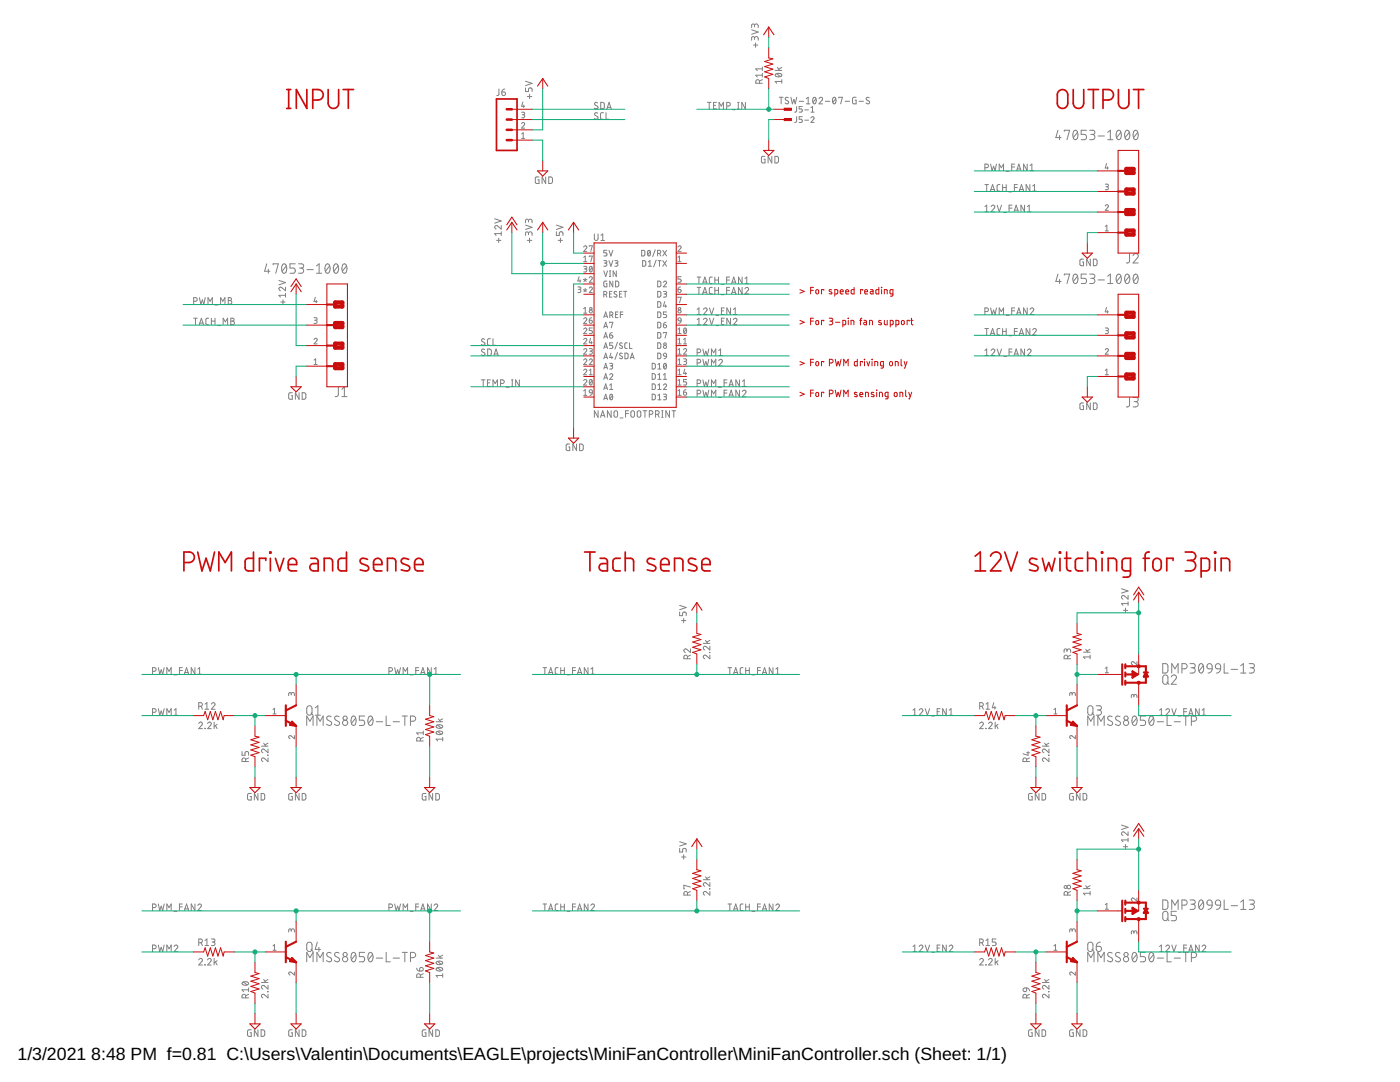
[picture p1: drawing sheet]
<svg xmlns="http://www.w3.org/2000/svg" width="279mm" height="216mm" viewBox="0 0 279 216" stroke-linecap="round" stroke-linejoin="round" font-family="sans-serif">
<defs><g id="words">
<g font-size="3.5">
<text x="3.5" y="211.4">1/3/2021</text>
<text x="18.2" y="211.4">8:48 PM f=0.81 C:\Users\Valentin\Documents\EAGLE\projects\MiniFanController\MiniFanController.sch (Sheet: 1/1)</text>
</g>
</g></defs>
<g fill="none" stroke="#808080" stroke-width=".2">
<path d="M99.6 17.8l-.1 1.1-.4 .2M100.1 18.4h.5a.37 .37 0 0 1 .3 .4 .37 .37 0 0 1-.4 .3 .37 .37 0 0 1-.4-.4zM100.7 17.8l-.3 .1-.3 .5M104.9 17.5v.8h.6v-.5a.36 .36 0 0 1 .3-.3 .36 .36 0 0 1 .4 .3v.5M104.9 16.2l1.3 .4-1.3 .5M105.2 19.3h.9M105.7 18.8v.9M150 5.9l1.3 .5-1.3 .4M150.4 9h.8M150.6 7.7a.37 .37 0 0 1 .4-.4 .37 .37 0 0 1 .3 .4v.3M150.6 7.9v-.4l-.4-.2-.2 .2v.5M150.6 5.1a.37 .37 0 0 1 .4-.3 .37 .37 0 0 1 .3 .3v.4"/>
<path d="M150.6 5.4v-.5l-.4-.1-.2 .1v.6M150.8 8.6v.8M151.6 16.6v-.3a.37 .37 0 0 0-.4-.4 .37 .37 0 0 0-.4 .4v.3h1.3M152.1 15.9l-.5 .3M152.1 15h-1.3l.3 .4M152.1 13.4v.7M152.1 14.6v.8M152.1 13.7h-1.3l.3 .4M154.7 14.1h1.3M154.8 14.8a.72 .72 0 0 1 1.2 .3 .84 .84 0 0 1-1.3-.1zM155 14.7l.7 .6M155.2 13.5l.4 .6"/>
<path d="M155.5 19.4h.8M155.9 19.4v1.3M156 16.3h-1.3l.3 .3M156 15.9v.7M156 13.5l-.6 .3M157.3 19.5l-.4-.1-.2 .3 .5 .5a.35 .35 0 0 1 0 .5 .35 .35 0 0 1-.5-.2M157.8 19.4l.3 1.3 .3-.9 .3 .9 .3-1.3M160.9 19.7l.4-.3v1.3M162.3 19.5l.1-.1a.66 .66 0 0 1 .5 .7 .66 .66 0 0 1-.5 .6l-.2-.6zM162.8 19.7l-.5 .7M163.4 19.7a.36 .36 0 0 1 .5-.3 .36 .36 0 0 1 .2 .6l-.7 .7h.8M166.3 19.5l.2-.1a.78 .78 0 0 1 0 1.3 .82 .82 0 0 1-.2-1.2z"/>
<path d="M166.8 19.7l-.6 .7M167.4 19.6v-.2h.7l-.3 1.3M170.9 19.4l-.7 .2-.1 .8 .2 .3h.6v-.7h-.3M173.5 19.5l-.5-.1-.1 .3 .5 .5a.35 .35 0 0 1 0 .5 .35 .35 0 0 1-.6-.2M104.1 24.7a.3 .3 0 0 1 .4-.2 .3 .3 0 0 1 .1 .4l-.5 .7h.6M104.1 22.4h.5l.1 .2-.1 .3h-.4M104.1 26.7l.3-.2v1.1M104.1 27.6h.6M104.4 20.3l-.3 .9h.6M104.4 22.9l.2 .1 .1 .3-.2 .2h-.4M104.5 21v.5M107.6 35.3l-.7 .1-.1 .9 .2 .3h.6v-.7h-.3"/>
<path d="M108.9 35.3v1.3l-.7-1.3v1.3M109.5 35.3h.5l.2 .2 .1 .7-.3 .4h-.5zM119.3 20.5l-.5-.1-.1 .3 .5 .5a.33 .33 0 0 1 0 .5 .33 .33 0 0 1-.5 0l-.1-.1M119.3 22.6a.33 .33 0 0 0-.5-.1 .33 .33 0 0 0 0 .5l.4 .2a.33 .33 0 0 1 0 .5 .33 .33 0 0 1-.5 0l-.1-.1M119.9 20.4l.5 .1 .2 .2v.8l-.2 .2h-.5zM120.4 22.5h-.4l-.2 .3 .1 .8 .5 .2M120.9 22.5v1.3h.6M121.1 21.7l.5-1.3 .4 1.3M121.2 21.4h.7M141.2 20.4h.7M141.5 20.4v1.3M142.4 21h.4"/>
<path d="M143 20.4h-.6v1.3h.6M143.5 21.7v-1.3l.4 .8 .5-.8v1.3M145 21.2h.4a.37 .37 0 0 0 .4-.4 .37 .37 0 0 0-.4-.4h-.4v1.3M146.2 21.9h.5M147.2 21.7h.3M147.2 20.4h.3M147.3 20.4v1.3M148.8 20.4v1.3l-.8-1.3v1.3M152.7 31.2l-.7 .1v.9l.1 .3h.6v-.7h-.2M154 31.2v1.3l-.7-1.3v1.3M154.6 31.2h.6l.1 .2v.9l-.1 .2h-.6zM159 21.3v.9l-.4 .2"/>
<path d="M159 23.3v1l-.4 .1M159.5 20.2h.9M160.1 21.3h-.6v.4h.4a.33 .33 0 0 1 .2 .4 .33 .33 0 0 1-.2 .3h-.4M160.1 23.3h-.6v.5h.4a.33 .33 0 0 1 .2 .3 .33 .33 0 0 1-.2 .3h-.4M160.6 21.9h.8M160.6 24h.8M160.9 20.7h.7M161.8 23.5a.31 .31 0 0 1 .5-.2 .31 .31 0 0 1 .1 .5l-.6 .6h.7M161.8 22.4h.7M161.8 21.5l.4-.2v1.1M164.7 20.2h.9M168.7 20.2h.8"/>
<path d="M171.4 20.2h.9M196.6 33.5h.3a.36 .36 0 0 0 .4-.4 .36 .36 0 0 0-.4-.4h-.3v1.4M196.6 36.8h.7M196.9 36.8v1.3M197.7 38.1l.4-1.3 .4 1.3M197.7 32.7l.3 1.4 .3-.9 .3 .9 .3-1.4M197.8 37.8h.6M199.4 34.1v-1.4l.4 .8 .5-.8v1.4M199.6 36.8l-.5 .1-.1 .2v.9l.6 .1M200.1 36.8v1.3M200.1 37.4h.7M200.8 34.2h.6"/>
<path d="M200.8 36.8v1.3M201.3 38.3h.6M201.9 33.3h.6M202.4 37.4h.6M202.5 32.7h-.6v1.4M202.9 34.1l.4-1.4 .5 1.4M203 33.7h.7M203 36.8h-.6v1.3M203.4 38.1l.5-1.3 .4 1.3M203.5 37.8h.7M205 32.7v1.4l-.7-1.4v1.4M205.5 36.8v1.3l-.7-1.3v1.3"/>
<path d="M205.6 33l.3-.3v1.4M205.6 34.1h.7M206.1 38.1h.7M206.1 37.1l.4-.3v1.3M211.1 26l-.4 1.5h1.1M211.5 27v.9M212.4 26.2v-.2h1.1l-.6 1.9M214.3 26.1l.3-.1a1.1 1.1 0 0 1 0 1.9 1.21 1.21 0 0 1-.3-1.8zM215 26.4l-.8 1.1M216.8 26h-1v.8h.6a.54 .54 0 0 1 .4 .5 .54 .54 0 0 1-.4 .6h-.6M217.5 26h.6a.41 .41 0 0 1 .4 .4 .41 .41 0 0 1-.4 .4h-.4M218 26.8a.53 .53 0 0 1 .5 .5 .53 .53 0 0 1-.5 .6h-.5"/>
<path d="M219.2 27.1h1.2M220.6 36.7l.5 .1 .1 .1-.1 .3-.4 .1M220.8 32.6l-.2 .9h.6M220.9 37.3l.2 .1v.4l-.5 .1M221 33.3v.5M221.1 27.9h1M221.1 26.4l.5-.4v1.9M223 26.1l.3-.1a1.1 1.1 0 0 1 0 1.9 1.17 1.17 0 0 1-.3-1.8zM223.7 26.4l-.9 1.1M224.7 26.1l.3-.1a1.1 1.1 0 0 1 0 1.9 1.19 1.19 0 0 1-.3-1.8zM225.4 26.4l-.9 1.1M226.4 26.1l.2-.1a1.1 1.1 0 0 1 0 1.9 1.21 1.21 0 0 1-.2-1.8z"/>
<path d="M227.1 26.4l-.9 1.1M39.8 59.4l.3 1.3 .3-.9 .3 .9 .3-1.3M45.6 59.4l.5 .1v.4l-.2 .1a.37 .37 0 0 1 .4 .3 .37 .37 0 0 1-.4 .4h-.3zM45.6 60h.3M53.2 52.6l-.4 1.5h1.1M53.6 53.7v.8M54.5 52.9v-.3h1l-.5 1.9M55.7 56l1.3 .4-1.3 .4M56.4 52.8l.3-.2a1.1 1.1 0 0 1 0 1.9 1.17 1.17 0 0 1-.3-1.7zM56.5 59.8v.9M57 57.3v.7l-.8-.6a.36 .36 0 0 0-.5 .1 .36 .36 0 0 0 .3 .5M57 58.9h-1.3l.3 .4"/>
<path d="M57 58.5v.8M57.1 53.1l-.8 1M58.9 52.6h-1v.9h.6a.53 .53 0 0 1 .4 .5 .53 .53 0 0 1-.4 .5h-.6M59.6 52.6h.6a.42 .42 0 0 1 .4 .5 .42 .42 0 0 1-.4 .4h-.4M60.1 53.5a.52 .52 0 0 1 .5 .5 .52 .52 0 0 1-.5 .5h-.5M61.3 53.8h1.2M62.9 59.3l-.2 .9h.6M63.1 59.9v.5M63.2 54.5h1M63.2 53.1l.5-.5v1.9M65.1 52.8l.3-.2a1.1 1.1 0 0 1 0 1.9 1.17 1.17 0 0 1-.3-1.7zM65.8 53.1l-.9 1"/>
<path d="M66.8 52.8l.3-.2a1.1 1.1 0 0 1 0 1.9 1.19 1.19 0 0 1-.3-1.7zM67.5 53.1l-.9 1M68.5 52.8l.2-.2a1.1 1.1 0 0 1 0 1.9 1.21 1.21 0 0 1-.2-1.7zM69.2 53.1l-.9 1M98.7 43.6l1.3 .5-1.3 .4M99.1 48h.9M99.5 47.5v.9M100 45v.7l-.7-.6a.36 .36 0 0 0-.5 .1 .36 .36 0 0 0 .2 .5M100 46.6h-1.3l.3 .4M100 46.2v.8M104.9 44.9l1.3 .5-1.3 .4M105.2 48h.9"/>
<path d="M105.5 46.6a.36 .36 0 0 1 .3-.4 .36 .36 0 0 1 .4 .4v.4M105.5 46.8l-.1-.4-.3-.1-.2 .1v.6M105.5 44.1a.36 .36 0 0 1 .3-.4 .36 .36 0 0 1 .4 .4v.3M105.5 44.3l-.1-.4-.3-.2-.2 .2v.5M105.7 47.5v.9M111 46.2v.8h.6v-.5a.38 .38 0 0 1 .4-.3 .38 .38 0 0 1 .4 .3v.5M111 44.9l1.4 .5-1.4 .4M111.4 48h.9M111.8 47.5v.9M115.3 57.3h.5l.1 .1-.1 .3h-.4M115.6 55.2l-.3 .9h.6M115.6 57.7l.3 .2v.2l-.1 .3h-.5"/>
<path d="M115.8 55.8v.5M116.4 57.8l.4 .1M116.4 55.8l.4 .1M116.5 53.1l.5 .1 .1 .1v.3l-.5 .1M116.5 49.3a.32 .32 0 0 1 .4-.2 .32 .32 0 0 1 .1 .5l-.5 .6h.6M116.5 52.2h.6M116.5 51.4l.3-.3v1.1M116.8 55.5v.4M116.8 57.6v.3M116.8 57.9l.2 .3M116.8 57.9l-.3 .3M116.8 55.9l.2 .3"/>
<path d="M116.8 55.9l-.3 .3M116.8 53.7l.3 .1v.4l-.6 .1M117.1 57.8l-.3 .1M117.1 55.8l-.3 .1M117.6 57.5a.3 .3 0 0 1 .4-.2 .3 .3 0 0 1 .1 .4l-.5 .7h.6M117.6 55.5a.3 .3 0 0 1 .4-.3 .3 .3 0 0 1 .1 .5l-.5 .6h.6M117.6 51.2v-.1h.6l-.3 1.1M117.6 49.2v-.2h.6l-.3 1.2M117.7 53.2l.2-.1a.65 .65 0 0 1 0 1.2 .74 .74 0 0 1-.2-1.1zM118.2 53.4l-.5 .6M118.6 46.7v.9a.37 .37 0 0 0 .4 .4 .37 .37 0 0 0 .4-.4v-.9M119.9 47l.4-.3v1.3"/>
<path d="M119.9 48h.7M120.5 58.8l.6-.1v-.4l-.6-.2v1.2M120.5 52h.5l.1 .2-.1 .3h-.4M120.5 54.1l.4 1.1 .3-1.1M120.8 52.5l.3 .2v.3l-.6 .1M120.9 58.8l.2 .5M121.1 56.1l-.6 .1v.8l.1 .2h.5v-.6h-.2M121.1 50h-.6v.4h.4a.33 .33 0 0 1 .2 .4 .33 .33 0 0 1-.2 .3h-.4M121.5 50l.4 1.1 .4-1.1M121.5 52l.4 1.1 .4-1.1M121.6 55.2h.3M121.6 54.1h.3"/>
<path d="M121.6 58.7h.4M121.8 54.1v1.1M122.1 58.1h-.5v1.2h.5M122.3 56.1v1.1l-.6-1.1v1.1M122.7 52h.5l.1 .2-.1 .3h-.4M122.9 56.1h.4l.2 .2v.7l-.2 .2h-.4zM123 54.1v1.1l-.6-1.1v1.1M123 52.5l.3 .1v.4l-.6 .1M123.1 58.3a.28 .28 0 0 0-.5-.1 .28 .28 0 0 0 .1 .4l.3 .2a.31 .31 0 0 1 0 .5 .31 .31 0 0 1-.5-.2M123.6 58.7h.4M124.1 58.1h-.5v1.2h.5M124.5 58.1h.6"/>
<path d="M124.8 58.1v1.2M128.1 50h.4l.2 .1v.8l-.2 .2h-.4zM128.2 52h.5l.2 .2v.7l-.2 .2h-.5zM129.3 50h.1a.56 .56 0 0 1 .4 .5 .56 .56 0 0 1-.4 .6l-.2-.6zM129.4 53.1h.6M129.4 52.3l.3-.3v1.1M129.8 50.2l-.5 .6M130.8 49.8l-.5 1.4M131 51.9l-.5 1.4M131.2 50.6l.6-.1v-.4l-.6-.1v1.1M131.3 56.1h.4l.2 .2v.7l-.2 .2h-.4zM131.3 58.1l.4 .1 .2 .1v.7l-.2 .2-.4 .1z"/>
<path d="M131.3 52h.6M131.6 50.6l.3 .5M131.6 52v1.1M132.3 50l.7 1.1M132.3 52l.7 1.1M132.4 56.3a.31 .31 0 0 1 .4-.2 .31 .31 0 0 1 .1 .5l-.5 .6h.6M132.4 58.1l.5 .1 .1 .2-.1 .2-.4 .1M132.7 58.7l.3 .1v.4l-.6 .1M133 50l-.7 1.1M133 52l-.7 1.1M135.3 49.3a.32 .32 0 0 1 .4-.2 .32 .32 0 0 1 .1 .5l-.5 .6h.6M135.3 57.7h.4a.32 .32 0 0 1 .2 .4 .32 .32 0 0 1-.3 .3 .32 .32 0 0 1-.3-.3z"/>
<path d="M135.3 51.4l.3-.3v1.1M135.3 52.2h.6M135.3 59.4v-.1h.6l-.3 1.1M135.8 57.3l-.4 .1-.1 .3M135.9 55.2h-.6v.5h.4a.32 .32 0 0 1 .2 .3 .32 .32 0 0 1-.2 .3h-.4M139.1 55.3h.7M139.1 57.3h.7M139.5 55.3v1.3M139.5 57.3v1.4M140.2 56.6l.5-1.3 .4 1.3M140.2 58.7l.5-1.4 .4 1.4M140.3 56.3h.7"/>
<path d="M140.3 58.3h.7M142.2 55.3h-.5l-.1 .3v.8l.6 .2M142.2 57.3l-.5 .1-.1 .2v.9l.6 .2M142.7 55.9h.7M142.7 55.3v1.3M142.7 57.3v1.4M142.7 57.9h.7M143.4 55.3v1.3M143.4 57.3v1.4M143.9 56.7h.6M143.9 58.8h.6M145 55.9h.6"/>
<path d="M145 57.9h.6M145.6 55.3h-.6v1.3M145.6 57.3h-.6v1.4M146 56.6l.4-1.3 .5 1.3M146 58.7l.4-1.4 .5 1.4M146.1 56.3h.7M146.1 58.3h.7M148.1 55.3v1.3l-.7-1.3v1.3M148.1 57.3v1.4l-.7-1.4v1.4M148.7 57.6a.36 .36 0 0 1 .5-.2 .36 .36 0 0 1 .1 .5l-.6 .8h.7M148.7 56.6h.7M148.7 55.6l.3-.3v1.3"/>
<path d="M196.6 41.2l.3-.3v1.3M196.6 42.2h.7M197.8 41.2a.37 .37 0 0 1 .5-.2 .37 .37 0 0 1 .1 .5l-.6 .7h.7M199 40.9l.4 1.3 .5-1.3M200.3 42.4h.6M201.4 41.5h.6M202 40.9h-.6v1.3M202.4 42.2l.4-1.3 .4 1.3M202.5 41.9h.6M204.5 40.9v1.3l-.7-1.3v1.3M205 42.2h.8M205 41.2l.4-.3v1.3"/>
<path d="M211.1 54.7l-.4 1.5h1.1M211.5 55.8v.8M212.4 54.9v-.2h1.1l-.6 1.9M214.3 54.8l.3-.1a1.1 1.1 0 0 1 0 1.9 1.21 1.21 0 0 1-.3-1.8zM215 55.1l-.8 1.1M216.2 51.7h-.5l-.1 .2-.1 .8 .2 .3h.5v-.7h-.2M216.8 54.7h-1v.8h.6a.53 .53 0 0 1 .4 .6 .53 .53 0 0 1-.4 .5h-.6M217.5 54.7h.6a.42 .42 0 0 1 .4 .4 .42 .42 0 0 1-.4 .4h-.4M217.6 51.7v1.3l-.7-1.3v1.3M218 55.5a.52 .52 0 0 1 .5 .6 .52 .52 0 0 1-.5 .5h-.5M218.2 51.7h.5l.2 .2v.7l-.2 .4h-.5zM219.2 55.9h1.2"/>
<path d="M220.6 41.1a.31 .31 0 0 1 .4-.2 .31 .31 0 0 1 .1 .4l-.5 .7h.6M220.6 45.2l.3-.3v1.2M220.6 46.1h.6M221.1 56.6h1M221.1 55.1l.5-.4v1.9M223 54.8l.3-.1a1.1 1.1 0 0 1 0 1.9 1.17 1.17 0 0 1-.3-1.8zM223.7 55.1l-.9 1.1M224.7 54.8l.3-.1a1.1 1.1 0 0 1 0 1.9 1.19 1.19 0 0 1-.3-1.8zM225.4 55.1l-.9 1.1M225.4 50.6v1.6l-.2 .3h-.4M226.1 51a.51 .51 0 0 1 .8-.4 .51 .51 0 0 1 .1 .8l-.9 1.1h1.1M226.4 54.8l.2-.1a1.1 1.1 0 0 1 0 1.9 1.21 1.21 0 0 1-.2-1.8z"/>
<path d="M227.1 55.1l-.9 1.1M38.7 60.1h.3a.36 .36 0 0 0 .4-.3 .36 .36 0 0 0-.4-.4h-.3v1.3M38.7 63.5h.7M39 63.5v1.3M39.8 64.8l.4-1.3 .4 1.3M39.9 64.5h.6M41.5 60.7v-1.3l.4 .7 .5-.7v1.3M41.7 63.5h-.4l-.2 .3v.8l.2 .2h.4M42.2 63.5v1.3M42.2 64.1h.7M42.9 60.9h.6M42.9 63.5v1.3"/>
<path d="M43.4 65h.6M44 60.7v-1.3l.5 .7 .4-.7v1.3M44.5 64.8v-1.3l.5 .7 .4-.7v1.3M46.1 63.5l.6 .1v.3l-.3 .2a.37 .37 0 0 1 .4 .3 .37 .37 0 0 1-.4 .4h-.3zM46.1 64.1h.3M56 60.3h.9M58.3 78.4l-.6 .1-.1 .9 .2 .3h.5v-.7h-.2M59.7 78.4v1.3l-.8-1.3v1.3M60.3 78.4h.5l.2 .2v.7l-.2 .4h-.5zM62.7 67.8a.31 .31 0 0 1 .4-.3 .31 .31 0 0 1 .1 .5l-.5 .6h.6M62.7 63.4h.5l.1 .2-.1 .3h-.4M62.7 72.7h.6"/>
<path d="M62.7 71.9l.3-.3v1.1M63 63.9l.2 .1v.4l-.5 .1M67.5 77.3v1.6l-.2 .2h-.4M68.2 79.1h1.1M68.2 77.7l.5-.4v1.8M96.1 75.8h.7M96.4 75.8v1.3M96.7 69.7h-.4l-.2 .2 .5 .5a.32 .32 0 0 1 .1 .5 .32 .32 0 0 1-.5 0l-.1-.1M96.7 67.7l-.4-.1-.2 .3 .5 .5a.32 .32 0 0 1 .1 .4 .32 .32 0 0 1-.5 0l-.1-.1M97.3 76.4h.4M97.3 69.6l.5 .1 .2 .2 .1 .7-.3 .3-.5 .1zM97.9 67.6h-.5l-.1 .3v.8l.2 .2h.4"/>
<path d="M97.9 75.8h-.6v1.3h.6M98.4 67.6v1.3h.6M98.4 77.1v-1.3l.4 .7 .5-.7v1.3M98.6 71l.4-1.4 .4 1.4M98.7 70.6h.6M99.9 76.5h.4a.36 .36 0 0 0 .3-.3 .36 .36 0 0 0-.3-.4h-.4v1.3M101 77.3h.6M102.1 75.8h.3M102.1 77.1h.3M102.2 75.8v1.3M103.7 75.8v1.3l-.8-1.3v1.3M116.5 75.9a.31 .31 0 0 1 .4-.2 .31 .31 0 0 1 .1 .5l-.5 .6h.6"/>
<path d="M116.5 73.9a.31 .31 0 0 1 .4-.2 .31 .31 0 0 1 .1 .4l-.5 .7h.6M116.5 71.9a.32 .32 0 0 1 .4-.3 .32 .32 0 0 1 .1 .5l-.5 .6h.6M116.5 69.8a.32 .32 0 0 1 .4-.2 .32 .32 0 0 1 .1 .5l-.5 .6h.6M116.5 67.8a.32 .32 0 0 1 .4-.3 .32 .32 0 0 1 .1 .5l-.5 .6h.6M116.5 65.7a.32 .32 0 0 1 .4-.2 .32 .32 0 0 1 .1 .5l-.5 .6h.6M116.5 63.6a.32 .32 0 0 1 .4-.2 .32 .32 0 0 1 .1 .5l-.5 .6h.6M116.5 61.6l.3-.3v1.2M116.5 78l.3-.3v1.2M116.5 78.9h.6M116.5 62.5h.6M117.6 71.9a.31 .31 0 0 1 .4-.3 .31 .31 0 0 1 .1 .5l-.5 .6h.6M117.6 69.6h.5l.1 .1-.1 .3-.4 .1"/>
<path d="M117.6 63.9h.4a.31 .31 0 0 1 .2 .3 .31 .31 0 0 1-.3 .3 .31 .31 0 0 1-.3-.3zM117.6 74.8h.6M117.6 73.9l.3-.2v1.1M117.7 77.8h.4l.1 .6-.5-.1zM117.7 75.8l.2-.1a.6 .6 0 0 1 .3 .6 .6 .6 0 0 1-.4 .5l-.2-.5zM117.9 67.5l-.3 .9h.6M117.9 70.1l.3 .1v.2l-.2 .3h-.4M118 68.1v.5M118.1 63.4l-.3 .1-.2 .4M118.2 75.9l-.5 .7M118.2 78.4l-.1 .3-.4 .2M118.2 65.4h-.6v.6h.4a.31 .31 0 0 1 .2 .3 .31 .31 0 0 1-.2 .3h-.4"/>
<path d="M120.5 79.8l.4-1.1 .3 1.1M120.5 77.7l.4-1.1 .3 1.1M120.5 75.7l.4-1.2 .3 1.2M120.5 73.6l.4-1.1 .3 1.1M120.5 71.6l.4-1.1 .3 1.1M120.5 69.5l.4-1.1 .3 1.1M120.5 67.5l.4-1.1 .3 1.1M120.5 65.4l.4-1.1 .3 1.1M120.5 63.4l.4-1.1 .3 1.1M120.6 79.5h.6M120.6 77.4h.6M120.6 75.4h.6"/>
<path d="M120.6 73.3h.6M120.6 71.3h.6M120.6 69.3h.6M120.6 67.2h.6M120.6 65.2h.6M120.6 63.1h.6M121.7 74.8a.31 .31 0 0 1 .4-.2 .31 .31 0 0 1 .1 .5l-.5 .6h.6M121.7 72.5h.3l.3 .2-.1 .3h-.4M121.7 66.9h.3a.31 .31 0 0 1 .3 .3 .31 .31 0 0 1-.4 .3 .31 .31 0 0 1-.2-.3zM121.7 64.4v-.1h.6l-.3 1.1M121.7 77.7h.6M121.7 76.9l.3-.3v1.1"/>
<path d="M121.7 62.9l.6-.1v-.4l-.6-.1v1.1M121.8 78.7h.1a.56 .56 0 0 1 .4 .5 .56 .56 0 0 1-.4 .6l-.2-.6zM121.9 70.5l-.2 .8h.6M122 73l.2 .1 .1 .3-.2 .2h-.4M122.1 62.9l.2 .5M122.1 71.1v.5M122.2 66.4l-.4 .1-.1 .4M122.2 78.9l-.5 .6M122.3 68.4h-.6v.5h.3a.32 .32 0 0 1 .3 .3 .32 .32 0 0 1-.3 .3h-.3M122.9 62.8h.3M123.2 70.3l-.5 1.4M123.2 68.3l-.5 1.4"/>
<path d="M123.3 62.3h-.4v1.1h.4M123.8 62.8h.5M124.2 70.5h-.4l-.1 .2 .5 .5v.2l-.2 .2-.4-.2M124.2 68.5l-.4-.1-.1 .3 .4 .4a.29 .29 0 0 1 0 .4 .29 .29 0 0 1-.4 0l-.1-.1M124.3 62.3h-.5v1.1M124.7 70.5h.5l.1 .2v.7l-.1 .2h-.5zM125.2 68.4h-.4l-.1 .3v.7l.5 .1M125.6 68.4v1.1h.6M125.8 71.6l.4-1.1 .4 1.1M125.9 71.3h.6M130.2 72.5h.3l.3 .2v.7l-.2 .2h-.4zM130.2 74.5l.4 .1 .2 .1v.8l-.3 .2h-.3z"/>
<path d="M130.2 76.6h.4l.2 .2v.7l-.2 .2h-.4zM130.2 78.7h.4l.2 .1v.8l-.2 .2h-.4zM131.3 60.2h.4l.2 .2v.6l-.2 .3h-.4zM131.3 62.3h.4l.2 .1v.7l-.2 .3h-.4zM131.3 64.3h.4l.2 .2v.7l-.2 .2h-.4zM131.3 66.4h.4l.2 .1v.8l-.2 .2h-.4zM131.3 68.4h.4l.2 .2v.7l-.2 .2h-.4zM131.3 70.5h.4l.2 .2v.7l-.2 .2h-.4zM131.3 72.7l.3-.2v1.1M131.3 74.8l.3-.3v1.2M131.3 76.9l.3-.3v1.1M131.3 78.9l.3-.2v1.1"/>
<path d="M131.3 73.6h.6M131.3 75.7h.6M131.3 77.7h.6M131.3 79.8h.6M132.4 64.8h.4a.31 .31 0 0 1 .2 .4 .31 .31 0 0 1-.3 .2 .31 .31 0 0 1-.3-.3zM132.4 76.9a.31 .31 0 0 1 .4-.3 .31 .31 0 0 1 .1 .5l-.5 .6h.6M132.4 78.7h.5l.1 .1-.1 .3-.4 .1M132.4 66.5v-.1h.6l-.3 1.1M132.4 75.7h.6M132.4 74.8l.3-.3v1.2M132.5 70.5h.4l.1 .6-.5-.1-.1-.2zM132.5 72.6l.1-.1a.58 .58 0 0 1 .4 .6 .58 .58 0 0 1-.4 .5l-.2-.5z"/>
<path d="M132.7 60.2l-.3 .9h.6M132.7 79.2l.3 .1v.4l-.6 .1M132.8 60.8v.5M132.9 64.3l-.4 .2-.1 .3M133 72.7l-.5 .7M133 62.3h-.6v.5h.4a.31 .31 0 0 1 .2 .3 .31 .31 0 0 1-.2 .3h-.4M133 71.1l-.1 .3-.4 .2M135.3 65.7l.3-.3v1.2M135.3 67.8l.3-.3v1.1M135.3 69.8l.3-.2v1.1M135.3 71.9l.3-.3v1.1M135.3 73.9l.3-.2v1.1"/>
<path d="M135.3 75.9l.3-.2v1.1M135.3 78l.3-.3v1.2M135.3 66.6h.6M135.3 68.6h.6M135.3 70.7h.6M135.3 72.7h.6M135.3 74.8h.6M135.3 76.8h.6M135.3 78.9h.6M135.4 63.5h.4l.1 .5-.6-.1zM135.9 64l-.2 .4-.3 .1M136.4 69.8a.31 .31 0 0 1 .5-.2 .31 .31 0 0 1 0 .5l-.5 .6h.6"/>
<path d="M136.4 71.6h.5l.1 .2v.2l-.5 .1M136.4 78.3h.4a.31 .31 0 0 1 .2 .3 .31 .31 0 0 1-.3 .3 .31 .31 0 0 1-.3-.3zM136.4 68.6h.6M136.4 67.8l.3-.3v1.1M136.5 65.5h.1a.58 .58 0 0 1 .4 .5 .58 .58 0 0 1-.4 .6l-.2-.6zM136.7 73.7l-.3 .8h.6M136.7 72.1l.3 .1v.3l-.1 .2h-.5M136.8 74.3v.5M136.9 77.7a.47 .47 0 0 0-.5 .6M137 65.7l-.5 .6M137 75.7h-.6v.5h.4a.32 .32 0 0 1 .2 .3 .32 .32 0 0 1-.2 .3h-.4M139.1 76.5h.4a.36 .36 0 0 0 .3-.3 .36 .36 0 0 0-.3-.4h-.4v1.3"/>
<path d="M139.1 78.6h.4a.36 .36 0 0 0 .3-.4 .36 .36 0 0 0-.3-.3h-.4v1.3M139.1 70.4h.4a.37 .37 0 0 0 .3-.4 .37 .37 0 0 0-.3-.4h-.4v1.4M139.1 72.4h.4a.37 .37 0 0 0 .3-.3 .37 .37 0 0 0-.3-.4h-.4v1.3M139.1 62.8h.7M139.1 64.8h.7M139.1 61.7l.4-.3v1.4M139.1 63.8l.4-.3v1.3M140.3 75.8l.3 1.3 .3-.9 .3 .9 .3-1.3M140.3 77.9l.3 1.3 .3-.9 .3 .9 .3-1.3M140.3 69.6l.3 1.4 .3-.9 .3 .9 .3-1.4M140.3 71.7l.3 1.3 .3-.9 .3 .9 .3-1.3M140.4 61.7a.36 .36 0 0 1 .5-.2 .36 .36 0 0 1 .1 .5l-.6 .8h.7"/>
<path d="M140.4 63.8a.36 .36 0 0 1 .5-.3 .36 .36 0 0 1 .1 .6l-.6 .7h.7M141.6 61.4l.4 1.4 .5-1.4M141.6 63.5l.4 1.3 .5-1.3M142 71v-1.4l.4 .8 .5-.8v1.4M142 73v-1.3l.4 .7 .5-.7v1.3M142 77.1v-1.3l.4 .7 .5-.7v1.3M142 79.2v-1.3l.4 .7 .5-.7v1.3M142.9 65h.5M142.9 62.9h.5M143.4 79.3h.6M143.4 77.3h.6M143.4 72a.36 .36 0 0 1 .6-.3 .36 .36 0 0 1 .1 .6l-.7 .7h.8"/>
<path d="M143.4 71h.8M143.4 69.9l.4-.3v1.4M144 64.1h.4M144 62h.4M144.5 76.4h.6M144.5 78.4h.6M144.5 61.4h-.5v1.4h.5M144.5 63.5h-.5v1.3h.5M145.1 75.8h-.6v1.3M145.1 77.9h-.6v1.3M145.5 77.1l.4-1.3 .4 1.3M145.5 79.2l.4-1.3 .4 1.3"/>
<path d="M145.6 76.8h.6M145.6 78.8h.6M145.8 61.4v1.4l-.7-1.4v1.4M145.8 63.5v1.3l-.7-1.3v1.3M146.4 63.8a.36 .36 0 0 1 .5-.3 .36 .36 0 0 1 .1 .6l-.6 .7h.7M146.4 62.8h.7M146.4 61.7l.3-.3v1.4M147.6 75.8v1.3l-.7-1.3v1.3M147.6 77.9v1.3l-.7-1.3v1.3M148.2 78.1a.35 .35 0 0 1 .5-.2 .35 .35 0 0 1 .1 .5l-.6 .8h.7M148.2 76.1l.3-.3v1.3M148.2 77.1h.7"/>
<path d="M196.6 62.2h.3a.36 .36 0 0 0 .4-.4 .36 .36 0 0 0-.4-.4h-.3v1.4M196.6 69.9l.3-.3v1.4M196.6 65.6h.7M196.6 71h.7M196.9 65.6v1.3M197.7 66.9l.4-1.3 .4 1.3M197.7 61.4l.3 1.4 .3-.9 .3 .9 .3-1.4M197.8 66.5h.6M197.8 69.9a.37 .37 0 0 1 .5-.2 .37 .37 0 0 1 .1 .5l-.6 .8h.7M199 69.6l.4 1.4 .5-1.4M199.4 62.8v-1.4l.4 .8 .5-.8v1.4M199.6 65.6h-.5l-.1 .2v.9l.2 .1 .4 .1"/>
<path d="M200.1 65.6v1.3M200.1 66.1h.7M200.3 71.1h.6M200.8 65.6v1.3M200.8 62.9h.6M201.3 67h.6M201.4 70.2h.6M201.9 62h.6M202 69.6h-.6v1.4M202.4 71l.4-1.4 .4 1.4M202.4 66.1h.6M202.5 70.6h.6"/>
<path d="M202.5 61.4h-.6v1.4M202.9 62.8l.4-1.4 .5 1.4M203 62.4h.7M203 65.6h-.6v1.3M203.4 66.9l.5-1.3 .4 1.3M203.5 66.5h.7M204.5 69.6v1.4l-.7-1.4v1.4M205 61.4v1.4l-.7-1.4v1.4M205 69.9a.37 .37 0 0 1 .6-.2 .37 .37 0 0 1 .1 .5l-.7 .8h.8M205.5 65.6v1.3l-.7-1.3v1.3M205.6 61.7a.36 .36 0 0 1 .5-.2 .36 .36 0 0 1 .1 .5l-.6 .8h.7M206.1 65.8a.36 .36 0 0 1 .5-.2 .36 .36 0 0 1 .1 .5l-.6 .8h.7"/>
<path d="M220.6 69.8a.31 .31 0 0 1 .4-.2 .31 .31 0 0 1 .1 .5l-.5 .6h.6M220.6 65.4l.5 .1 .1 .1-.1 .3-.4 .1M220.6 74.8h.6M220.6 73.9l.3-.2v1.1M220.8 61.3l-.2 .9h.6M220.9 66l.2 .1v.4l-.5 .1M221 62v.5M225.4 79.3v1.6l-.2 .3h-.4M226.1 79.3h.6a.41 .41 0 0 1 .5 .4 .41 .41 0 0 1-.5 .4h-.4M113.7 88.6l-.7 .2v.8l.2 .3h.5v-.7h-.2M115.1 88.6v1.3l-.8-1.3v1.3M115.7 88.6h.5l.2 .2v.9l-.2 .2h-.5z"/>
<path d="M119.4 82v1.3l-.8-1.3v1.3M119.8 83.3l.5-1.3 .4 1.3M120 82.9h.6M122 82v1.3l-.8-1.3v1.3M122.6 82.1l.4-.1 .2 .2 .1 .7a.36 .36 0 0 1-.4 .4 .36 .36 0 0 1-.4-.4zM123.7 83.4h.6M124.8 82.5h.6M125.4 82h-.6v1.3M126 82.1l.4-.1 .2 .2v.7a.36 .36 0 0 1-.3 .4 .36 .36 0 0 1-.4-.4zM127.3 82.1l.4-.1 .2 .2v.7a.36 .36 0 0 1-.4 .4 .36 .36 0 0 1-.3-.4zM128.3 82h.8M128.7 82v1.3"/>
<path d="M129.6 82.7h.3a.36 .36 0 0 0 .4-.4 .36 .36 0 0 0-.4-.3h-.3v1.3M130.8 82.7h.4a.36 .36 0 0 0 .4-.4 .36 .36 0 0 0-.4-.3h-.4v1.3M131.3 82.7l.3 .6M132.1 82h.2M132.1 83.3h.2M132.2 82v1.3M133.6 82v1.3l-.7-1.3v1.3M134.1 82h.7M134.5 82v1.3M216.2 80.4l-.6 .2-.1 .8 .2 .3h.5v-.7h-.2M217.6 80.4v1.3l-.7-1.3v1.3M218.2 80.4h.5l.2 .2v.8l-.2 .3h-.5z"/>
<path d="M226.6 80.1a.53 .53 0 0 1 .6 .6 .53 .53 0 0 1-.6 .5h-.5M223.8 117.5l1.3 .4-1.3 .4M225.1 118.8v.7l-.7-.6a.36 .36 0 0 0-.6 .1 .36 .36 0 0 0 .3 .5M30.4 133.9h.4a.36 .36 0 0 0 .4-.3 .36 .36 0 0 0-.4-.4h-.4v1.3M31.6 133.2l.3 1.3 .3-.9 .3 .9 .3-1.3M33.3 134.5v-1.3l.4 .7 .5-.7v1.3M34.7 134.7h.6M35.8 133.8h.6M36.4 133.2h-.6v1.3M36.8 134.5l.4-1.3 .5 1.3M36.9 134.2h.6M38.9 133.2v1.3l-.7-1.3v1.3"/>
<path d="M39.5 134.5h.7M39.5 133.5l.3-.3v1.3M58.1 138.5l.2-.3h.2l.2 .1 .1 .5M58.1 138.7v-.4l-.3-.1-.2 .2v.4M77.6 133.9h.4a.36 .36 0 0 0 .3-.3 .36 .36 0 0 0-.3-.4h-.4v1.3M78.8 133.2l.3 1.3 .3-.9 .2 .9 .3-1.3M80.5 134.5v-1.3l.4 .7 .4-.7v1.3M81.9 134.7h.5M83 133.8h.6M83.6 133.2h-.6v1.3M83.9 134.5l.5-1.3 .4 1.3M84.1 134.2h.6"/>
<path d="M86.1 133.2v1.3l-.8-1.3v1.3M86.6 133.5l.4-.3v1.3M86.6 134.5h.8M108.4 133.2h.7M108.7 133.2v1.3M109.5 134.5l.4-1.3 .4 1.3M109.6 134.2h.6M111.4 133.2h-.4l-.2 .3v.8l.6 .2M111.9 133.8h.7M111.9 133.2v1.3M112.6 133.2v1.3M113.2 134.7h.5"/>
<path d="M114.3 133.8h.6M114.9 133.2h-.6v1.3M115.2 134.5l.5-1.3 .4 1.3M115.3 134.2h.7M117.3 133.2v1.3l-.7-1.3v1.3M117.9 134.5h.7M117.9 133.5l.4-.3v1.3M135.6 122.1v.8h.6v-.5a.37 .37 0 0 1 .4-.3 .37 .37 0 0 1 .3 .3v.5M135.6 120.8l1.3 .4-1.3 .5M136 123.8h.9M136.4 123.4v.9M137.2 131.4v-.3a.36 .36 0 0 0-.4-.4 .36 .36 0 0 0-.3 .4v.3h1.3"/>
<path d="M137.8 129.5v.7l-.7-.6a.36 .36 0 0 0-.6 .1 .36 .36 0 0 0 .3 .5M137.8 130.7l-.6 .3M140.4 128.4h1.3M140.8 127.8l.4 .6M141.7 130.2h.1M141.7 130.7v.7l-.8-.6a.36 .36 0 0 0-.5 .1 .36 .36 0 0 0 .3 .5M141.7 128.9v.8l-.8-.6a.37 .37 0 0 0-.5 .1 .37 .37 0 0 0 .3 .5M141.7 127.8l-.6 .3M145.3 133.2h.7M145.6 133.2v1.3M146.4 134.5l.4-1.3 .5 1.3M146.5 134.2h.7"/>
<path d="M148.3 133.2h-.4l-.2 .3v.8l.6 .2M148.8 133.8h.7M148.8 133.2v1.3M149.5 133.2v1.3M150.1 134.7h.5M151.2 133.8h.6M151.8 133.2h-.6v1.3M152.1 134.5l.5-1.3 .4 1.3M152.3 134.2h.6M154.3 133.2v1.3l-.8-1.3v1.3M154.8 134.5h.8M154.8 133.5l.4-.3v1.3"/>
<path d="M212.9 129.8a.37 .37 0 0 1 .4-.3 .37 .37 0 0 1 .4 .3v.4M212.9 130v-.4l-.3-.1-.2 .1v.6M213.1 131.4v-.3a.36 .36 0 0 0-.4-.4 .36 .36 0 0 0-.3 .4v.3h1.3M213.7 130.7l-.6 .3M214 138.5l.1-.3h.3l.2 .1v.5M214 138.7v-.4l-.3-.1-.2 .1v.5M216.2 130.1h1.4M216.7 129.6l.4 .5M217.6 131.1h-1.4l.3 .3M217.6 130.7v.7M217.6 129.6l-.7 .3M220.6 133.4l.3-.3v1.1"/>
<path d="M220.6 134.2h.6M224.2 121.8h.9M224.6 121.3v.9M225.1 120.4h-1.3l.3 .4M225.1 120.1v.7M226.3 138.9l.1-.3h.3l.2 .1v.5M226.3 139.1l-.1-.5h-.2l-.2 .1v.5M226.9 132v.7l-.6-.6a.31 .31 0 0 0-.5 .1 .31 .31 0 0 0 .2 .5M232.1 132.4h.6l.4 .4v1.1l-.4 .4h-.6zM232.2 134.9l.3-.2 .5 .2 .1 1.1a.52 .52 0 0 1-.5 .6 .52 .52 0 0 1-.5-.6zM232.9 136.1l.4 .4M233.7 135.1a.52 .52 0 0 1 .8-.4 .52 .52 0 0 1 .1 .8l-.9 1h1.1"/>
<path d="M233.8 134.3v-1.9l.7 1.1 .6-1.1v1.9M235.9 133.5h.5a.52 .52 0 0 0 .5-.6 .52 .52 0 0 0-.5-.5h-.5v1.9M237.5 132.4h.6a.41 .41 0 0 1 .4 .4 .41 .41 0 0 1-.4 .4h-.4M238 133.2a.53 .53 0 0 1 .5 .6 .53 .53 0 0 1-.5 .5h-.5M239.4 132.5l.3-.1a1.13 1.13 0 0 1 0 1.9 1.19 1.19 0 0 1-.3-1.8zM240.1 132.8l-.8 1.1M241 132.6l.3-.2 .4 .1 .2 .3v.7l-.9-.2-.1-.3zM241.9 133.5l-.2 .5-.6 .3M242.7 132.6l.3-.2 .5 .2 .1 .9-.9-.2-.2-.3zM243.6 133.5l-.2 .5-.6 .3M244.3 132.4v1.9h.8M245.7 133.6h1.3"/>
<path d="M247.6 134.3h1.1M247.6 132.8l.5-.4v1.9M249.3 132.4h.6a.41 .41 0 0 1 .4 .4 .41 .41 0 0 1-.4 .4h-.4M249.8 133.2a.53 .53 0 0 1 .5 .6 .53 .53 0 0 1-.5 .5h-.5M30.4 142.1h.4a.36 .36 0 0 0 .4-.3 .36 .36 0 0 0-.4-.4h-.4v1.3M31.6 141.4l.3 1.3 .3-.8 .3 .8 .3-1.3M33.3 142.7v-1.3l.4 .7 .5-.7v1.3M34.8 142.7h.7M34.8 141.7l.3-.3v1.3M39.7 144.4a.36 .36 0 0 1 .5-.3 .36 .36 0 0 1 .1 .6l-.6 .7h.7M39.7 140.9h.3a.36 .36 0 0 0 .4-.3 .36 .36 0 0 0-.4-.4h-.3v1.3M40.1 140.9l.3 .6"/>
<path d="M40.9 145.3l.1 .1zM40.9 140.5l.4-.3v1.3M40.9 141.5h.8M41.4 144.4a.36 .36 0 0 1 .6-.3 .36 .36 0 0 1 .1 .6l-.7 .7h.8M42.2 140.5a.36 .36 0 0 1 .5-.3 .36 .36 0 0 1 .1 .6l-.6 .7h.7M42.7 144.1v1.3M43 144.8l.3 .6M43.3 144.5l-.6 .4M48.3 150v.7h.6v-.4a.36 .36 0 0 1 .4-.3 .36 .36 0 0 1 .3 .3v.4M49 152v-.4a.36 .36 0 0 0-.3-.4 .36 .36 0 0 0-.4 .4v.4h1.3M49.6 151.2l-.6 .3M50.1 158.3l-.7 .2v.9l.2 .2h.5v-.7h-.2"/>
<path d="M51.5 158.3v1.3l-.7-1.3v1.3M52.1 158.3l.5 .1 .2 .2v.8l-.2 .2h-.5zM52.2 148.9h1.3M52.6 148.3l.4 .6M53.4 150.7h.1zM53.5 151.2v.8l-.7-.7a.36 .36 0 0 0-.6 .1 .36 .36 0 0 0 .3 .6M53.5 149.5v.7l-.7-.6a.37 .37 0 0 0-.6 .1 .37 .37 0 0 0 .3 .5M53.5 148.3l-.6 .3M54.5 141.6l.3-.3v1.2M54.5 142.5h.6M58.3 158.3l-.6 .2-.1 .9 .2 .2h.5v-.7h-.2M58.8 146.8v.6l-.7-.5a.31 .31 0 0 0-.5 .1 .31 .31 0 0 0 .3 .4"/>
<path d="M59.7 158.3v1.3l-.8-1.3v1.3M60.3 158.3l.5 .1 .2 .2v.7l-.2 .3h-.5zM61.2 144.8v-1.9l.6 1 .7-1v1.9M61.3 141l.4-.2 .4 .2 .2 1.2a.53 .53 0 0 1-.6 .5 .53 .53 0 0 1-.5-.5zM62.1 142.3l.4 .4M62.9 141.2l.5-.4v1.9M62.9 142.7h1.1M63.2 144.8v-1.9l.7 1 .6-1v1.9M66.1 143a.47 .47 0 0 0-.7-.1 .47 .47 0 0 0 0 .8l.6 .3a.47 .47 0 0 1 .1 .7 .47 .47 0 0 1-.8-.1l-.1-.1M67.7 143a.47 .47 0 0 0-.8-.1 .47 .47 0 0 0 .1 .8l.6 .3a.47 .47 0 0 1 0 .7 .47 .47 0 0 1-.7-.1l-.2-.1M70.3 143l.3-.1a1.13 1.13 0 0 1 0 1.9 1.19 1.19 0 0 1-.3-1.8zM71 143.3l-.9 1"/>
<path d="M72.8 142.9h-1.1v.8h.6a.54 .54 0 0 1 .5 .5 .54 .54 0 0 1-.5 .6h-.6M73.6 143l.3-.1a1.1 1.1 0 0 1 0 1.9 1.19 1.19 0 0 1-.3-1.8zM74.4 143.3l-.9 1M75.1 144h1.3M77.1 142.9v1.9h.8M78.5 144h1.2M80.3 142.9h1M80.8 142.9v1.9M81.9 143.9h.5a.52 .52 0 0 0 .6-.5 .52 .52 0 0 0-.6-.5h-.5v1.9M83.9 147.8v-.3a.37 .37 0 0 0-.4-.4 .37 .37 0 0 0-.3 .4v.3h1.3M84.5 147.1l-.6 .3M84.5 146.2h-1.3l.3 .4"/>
<path d="M84.5 145.9v.7M85 158.3l-.7 .2v.9l.2 .2h.5v-.7h-.2M86.3 158.3v1.3l-.7-1.3v1.3M87 158.3l.5 .1 .2 .2v.8l-.2 .2h-.5zM87 144h1.3M87.1 146a.71 .71 0 0 1 1.2 .3 .82 .82 0 0 1-1.3-.1zM87.1 144.8a.73 .73 0 0 1 1.2 .3 .72 .72 0 0 1-1.2-.2zM87.3 145.9l.8 .6M87.3 144.7l.8 .6M87.5 143.4l.4 .6M88.3 147.5h-1.3l.3 .3M88.3 147.1v.7"/>
<path d="M88.3 143.4l-.6 .4M182.2 142.7h.7M182.2 141.7l.4-.3v1.3M183.5 141.7a.36 .36 0 0 1 .5-.3 .36 .36 0 0 1 .1 .6l-.6 .7h.7M184.6 141.4l.5 1.3 .4-1.3M185.9 142.9h.6M187 142h.5M187.6 141.4h-.6v1.3h.6M188.8 141.4v1.3l-.7-1.3v1.3M189.4 142.7h.8M189.4 141.7l.4-.3v1.3M195.5 144.4a.37 .37 0 0 1 .5-.3 .37 .37 0 0 1 .2 .6l-.7 .7h.8"/>
<path d="M195.5 140.9h.4a.36 .36 0 0 0 .4-.3 .36 .36 0 0 0-.4-.4h-.4v1.3M196 140.9l.3 .6M196.7 145.4h.1M196.8 141.5h.7M196.8 140.5l.3-.3v1.3M197.3 144.4a.36 .36 0 0 1 .5-.3 .36 .36 0 0 1 .1 .6l-.6 .7h.7M198.3 140.2l-.3 1h.8M198.5 140.9v.6M198.6 144.1v1.3M198.9 144.8l.3 .6M199.2 144.5l-.6 .4M204.9 152v-.4a.37 .37 0 0 0-.4-.4 .37 .37 0 0 0-.3 .4v.4h1.3"/>
<path d="M204.9 150.2h.6M205.2 150v.7l-1-.3M205.5 151.2l-.6 .3M206 158.3l-.7 .2v.9l.1 .2h.6v-.7h-.2M207.3 158.3v1.3l-.7-1.3v1.3M208 158.3l.5 .1 .2 .2v.8l-.2 .2h-.5zM208 148.9h1.3M208.5 148.3l.4 .6M209.3 150.7h.1M209.3 151.2v.8l-.7-.7a.36 .36 0 0 0-.5 .1 .36 .36 0 0 0 .2 .6M209.3 149.5v.7l-.7-.6a.36 .36 0 0 0-.5 .1 .36 .36 0 0 0 .2 .5M209.3 148.3l-.6 .3"/>
<path d="M210.3 142.5h.6M210.3 141.6l.4-.3v1.2M214.2 158.3l-.7 .2v.9l.2 .2h.5v-.7h-.2M214.6 146.8v.6l-.6-.5a.31 .31 0 0 0-.5 .1 .31 .31 0 0 0 .2 .4M215.5 158.3v1.3l-.7-1.3v1.3M216.2 158.3l.5 .1 .2 .2v.7l-.2 .3h-.5zM217.1 144.8v-1.9l.6 1 .6-1v1.9M217.2 141l.3-.2 .5 .2 .1 1.2a.52 .52 0 0 1-.5 .5 .52 .52 0 0 1-.5-.5zM217.9 142.3l.4 .4M218.8 140.8h.6a.42 .42 0 0 1 .4 .4 .42 .42 0 0 1-.4 .5h-.4M219.1 144.8v-1.9l.6 1 .7-1v1.9M219.3 141.7a.52 .52 0 0 1 .5 .5 .52 .52 0 0 1-.5 .5h-.5"/>
<path d="M222 143a.48 .48 0 0 0-.8-.1 .48 .48 0 0 0 .1 .8l.5 .3a.47 .47 0 0 1 .1 .7 .47 .47 0 0 1-.7-.1l-.2-.1M223.5 143a.47 .47 0 0 0-.7-.1 .47 .47 0 0 0 0 .8l.6 .3a.47 .47 0 0 1 .1 .7 .47 .47 0 0 1-.7-.1l-.2-.1M226.1 143l.3-.1a1.1 1.1 0 0 1 0 1.9 1.19 1.19 0 0 1-.3-1.8zM226.8 143.3l-.8 1M228.6 142.9h-1v.8h.6a.54 .54 0 0 1 .4 .5 .54 .54 0 0 1-.4 .6h-.6M229.5 143l.3-.1a1.1 1.1 0 0 1 0 1.9 1.17 1.17 0 0 1-.3-1.8zM230.2 143.3l-.8 1M230.9 144h1.3M231.4 141.7l.4-.3v1.3M231.4 142.7h.7M232.7 141.7a.37 .37 0 0 1 .5-.3 .37 .37 0 0 1 .1 .6l-.6 .7h.7M232.9 142.9v1.9h.9"/>
<path d="M233.9 141.4l.4 1.3 .4-1.3M234.3 144h1.3M235.1 142.9h.6M236.1 142.9h1.1M236.2 142h.6M236.6 142.9v1.9M236.8 141.4h-.6v1.3M237.2 142.7l.5-1.3 .4 1.3M237.3 142.4h.7M237.8 143.9h.5a.52 .52 0 0 0 .5-.5 .52 .52 0 0 0-.5-.5h-.5v1.9M239.3 141.4v1.3l-.7-1.3v1.3M239.9 142.7h.7"/>
<path d="M239.9 141.7l.4-.3v1.3M135.6 169.3v.7h.6v-.4a.37 .37 0 0 1 .4-.3 .37 .37 0 0 1 .3 .3v.4M135.6 168l1.3 .4-1.3 .4M136 171h.9M136.4 170.6v.8M137.2 178.6v-.4a.36 .36 0 0 0-.4-.3 .36 .36 0 0 0-.3 .3v.4h1.3M137.8 177l-1.3-.4v.8h.1M137.8 177.9l-.6 .3M140.4 175.5h1.3M140.8 175l.4 .5M141.7 177.3h.1M141.7 177.9v.7l-.8-.6a.36 .36 0 0 0-.5 .1 .36 .36 0 0 0 .3 .5"/>
<path d="M141.7 176.1v.7l-.8-.6a.36 .36 0 0 0-.5 .1 .36 .36 0 0 0 .3 .5M141.7 175l-.6 .3M213.1 178.6v-.4a.36 .36 0 0 0-.4-.3 .36 .36 0 0 0-.3 .3v.4h1.3M213.7 177.9l-.6 .3M216.2 177.3h1.4M216.7 176.7l.4 .6M217.6 177.9v.7M217.6 178.2h-1.4l.3 .4M217.6 176.7l-.7 .4M223.8 164.6l1.3 .5-1.3 .4M224.2 169h.9M224.6 168.5v.9"/>
<path d="M225.1 166v.7l-.7-.6a.36 .36 0 0 0-.6 .1 .36 .36 0 0 0 .3 .5M225.1 167.2v.8M225.1 167.6h-1.3l.3 .4M226.9 179.2v.6l-.6-.5a.31 .31 0 0 0-.5 .1 .31 .31 0 0 0 .2 .4M232.1 179.6h.6l.4 .3v1.2l-.4 .3-.6 .1zM237.5 179.6h.6a.42 .42 0 0 1 .4 .4 .42 .42 0 0 1-.4 .4h-.4M239.4 179.7l.3-.1a1.13 1.13 0 0 1 0 1.9 1.19 1.19 0 0 1-.3-1.8zM241 179.8l.3-.2h.4l.2 .3v.7l-.9-.1-.1-.3zM242.7 179.8l.3-.2 .5 .2 .1 .8-.9-.1-.2-.3zM244.3 179.6v1.9h.8M249.3 179.6h.6a.42 .42 0 0 1 .4 .4 .42 .42 0 0 1-.4 .4h-.4M30.4 181.1h.4a.36 .36 0 0 0 .4-.4 .36 .36 0 0 0-.4-.3h-.4v1.3"/>
<path d="M30.4 189.3h.4a.37 .37 0 0 0 .4-.4 .37 .37 0 0 0-.4-.3h-.4v1.3M31.6 180.4l.3 1.3 .3-.9 .3 .9 .3-1.3M31.6 188.6l.3 1.3 .3-.9 .3 .9 .3-1.3M33.3 181.7v-1.3l.4 .7 .5-.7v1.3M33.3 189.9v-1.3l.4 .7 .5-.7v1.3M34.7 181.8h.6M34.8 188.9a.36 .36 0 0 1 .5-.3 .36 .36 0 0 1 .1 .6l-.6 .7h.7M35.8 181h.6M36.4 180.4h-.6v1.3M36.8 181.7l.4-1.3 .5 1.3M36.9 181.4h.6M38.9 180.4v1.3l-.7-1.3v1.3"/>
<path d="M39.5 180.7a.36 .36 0 0 1 .5-.3 .36 .36 0 0 1 .1 .6l-.6 .7h.7M39.7 191.5a.36 .36 0 0 1 .5-.2 .36 .36 0 0 1 .1 .5l-.6 .8h.7M39.7 188.1h.3a.37 .37 0 0 0 .4-.4 .37 .37 0 0 0-.4-.3h-.3v1.3M40.1 188.1l.3 .6M40.9 192.5l.1 .1zM40.9 187.7l.4-.3v1.3M40.9 188.7h.8M41.4 191.5a.36 .36 0 0 1 .6-.2 .36 .36 0 0 1 .1 .5l-.7 .8h.8M42.2 187.4h.6l.1 .2-.1 .3-.5 .1M42.5 188a.36 .36 0 0 1 .4 .3 .36 .36 0 0 1-.4 .4h-.3M42.7 191.2v1.4M43 191.9l.3 .7"/>
<path d="M43.3 191.7l-.6 .4M48.4 196a.72 .72 0 0 1 1.2 .3 .72 .72 0 0 1-1.3-.2zM48.6 195.9l.7 .6M49 199.1v-.3a.36 .36 0 0 0-.3-.4 .36 .36 0 0 0-.4 .4v.3h1.3M49.6 197.1v.8M49.6 198.4l-.6 .3M49.6 197.5h-1.3l.3 .4M52.2 196h1.3M52.6 195.5l.4 .5M53.5 197.8h.1M53.5 198.4v.7l-.7-.6a.36 .36 0 0 0-.6 .1 .36 .36 0 0 0 .3 .5M53.5 196.6v.8l-.7-.7a.37 .37 0 0 0-.6 .1 .37 .37 0 0 0 .3 .6"/>
<path d="M53.5 195.5l-.6 .3M54.5 188.7l.3-.2v1.1M54.5 189.6h.6M58.1 185.7l.2-.3 .2-.1 .2 .2 .1 .5M58.1 185.8v-.3l-.3-.2-.2 .3v.4M58.8 194v.6l-.7-.6a.31 .31 0 0 0-.5 .1 .31 .31 0 0 0 .3 .5M61.2 191.9v-1.9l.6 1.1 .7-1.1v1.9M61.3 188.2l.4-.2 .4 .2 .2 1.2a.53 .53 0 0 1-.6 .5 .53 .53 0 0 1-.5-.5zM62.1 189.4l.4 .5M63.2 191.9v-1.9l.7 1.1 .6-1.1v1.9M63.3 188l-.4 1.4h1.1M63.6 189v.9"/>
<path d="M66.1 190.2a.47 .47 0 0 0-.7-.1 .47 .47 0 0 0 0 .7l.6 .3a.47 .47 0 0 1 .1 .7 .47 .47 0 0 1-.8 0l-.1-.1M67.7 190.2a.47 .47 0 0 0-.8-.1 .47 .47 0 0 0 .1 .7l.6 .3a.47 .47 0 0 1 0 .7 .47 .47 0 0 1-.7 0l-.2-.1M70.3 190.2l.3-.2a1.13 1.13 0 0 1 0 1.9 1.19 1.19 0 0 1-.3-1.7zM71 190.5l-.9 1M72.8 190h-1.1v.9h.6a.53 .53 0 0 1 .5 .5 .53 .53 0 0 1-.5 .5h-.6M73.6 190.2l.3-.2a1.1 1.1 0 0 1 0 1.9 1.19 1.19 0 0 1-.3-1.7zM74.4 190.5l-.9 1M75.1 191.2h1.3M77.1 190v1.9h.8M77.6 181.1h.4a.36 .36 0 0 0 .3-.4 .36 .36 0 0 0-.3-.3h-.4v1.3M78.5 191.2h1.2M78.8 180.4l.3 1.3 .3-.9 .2 .9 .3-1.3"/>
<path d="M80.3 190h1M80.5 181.7v-1.3l.4 .7 .4-.7v1.3M80.8 190v1.9M81.9 181.8h.5M81.9 191.1h.5a.53 .53 0 0 0 .6-.5 .53 .53 0 0 0-.6-.6h-.5v1.9M83 181h.6M83.2 193.2l.2 .5 .4 .1M83.6 180.4h-.6v1.3M83.8 193.1a.37 .37 0 0 1 .6 .1 .37 .37 0 0 1-.3 .6h-.3zM83.9 195v-.4a.37 .37 0 0 0-.4-.3 .37 .37 0 0 0-.3 .3v.4h1.3M83.9 181.7l.5-1.3 .4 1.3M84.1 181.4h.6"/>
<path d="M84.5 194.3l-.6 .3M86.1 180.4v1.3l-.8-1.3v1.3M86.6 180.7a.36 .36 0 0 1 .5-.3 .36 .36 0 0 1 .1 .6l-.6 .7h.8M87 191.2h1.3M87.1 193.2a.73 .73 0 0 1 1.2 .3 .72 .72 0 0 1-.7 .3 .72 .72 0 0 1-.5-.5zM87.1 191.9a.72 .72 0 0 1 1.2 .3 .72 .72 0 0 1-1.2-.2zM87.3 193.1l.8 .6M87.3 191.8l.8 .6M87.5 190.6l.4 .6M88.3 194.3v.7M88.3 194.6h-1.3l.3 .4M88.3 190.6l-.6 .3"/>
<path d="M108.4 180.4h.7M108.7 180.4v1.3M109.5 181.7l.4-1.3 .4 1.3M109.6 181.4h.6M111.4 180.4h-.4l-.2 .3v.8l.2 .2h.4M111.9 180.4v1.3M111.9 181h.7M112.6 180.4v1.3M113.2 181.8h.5M114.3 181h.6M114.9 180.4h-.6v1.3M115.2 181.7l.5-1.3 .4 1.3"/>
<path d="M115.3 181.4h.7M117.3 180.4v1.3l-.7-1.3v1.3M117.9 180.7a.36 .36 0 0 1 .5-.3 .36 .36 0 0 1 .1 .6l-.6 .7h.7M145.3 180.4h.7M145.6 180.4v1.3M146.4 181.7l.4-1.3 .5 1.3M146.5 181.4h.7M148.3 180.4h-.4l-.2 .3v.8l.2 .2h.4M148.8 180.4v1.3M148.8 181h.7M149.5 180.4v1.3M150.1 181.8h.5"/>
<path d="M151.2 181h.6M151.8 180.4h-.6v1.3M152.1 181.7l.5-1.3 .4 1.3M152.3 181.4h.6M154.3 180.4v1.3l-.8-1.3v1.3M154.8 180.7a.36 .36 0 0 1 .5-.3 .36 .36 0 0 1 .1 .6l-.6 .7h.8M182.2 189.9h.7M182.2 188.9l.4-.3v1.3M183.5 188.9a.36 .36 0 0 1 .5-.3 .36 .36 0 0 1 .1 .6l-.6 .7h.7M184.6 188.6l.5 1.3 .4-1.3M185.9 190h.6M187 189.2h.5"/>
<path d="M187.6 188.6h-.6v1.3h.6M188.8 188.6v1.3l-.7-1.3v1.3M189.4 188.9a.37 .37 0 0 1 .5-.3 .37 .37 0 0 1 .2 .6l-.7 .7h.8M195.5 191.5a.37 .37 0 0 1 .5-.2 .37 .37 0 0 1 .2 .5l-.7 .8h.8M195.5 188.1h.4a.37 .37 0 0 0 .4-.4 .37 .37 0 0 0-.4-.3h-.4v1.3M196 188.1l.3 .6M196.7 192.6h.1M196.8 188.7h.7M196.8 187.7l.3-.3v1.3M197.3 191.5a.36 .36 0 0 1 .5-.2 .36 .36 0 0 1 .1 .5l-.6 .8h.7M198.6 191.2v1.4M198.8 187.4h-.8v.6h.5a.36 .36 0 0 1 .3 .3 .36 .36 0 0 1-.3 .4h-.5"/>
<path d="M198.9 191.9l.3 .7M199.2 191.7l-.6 .4M204.3 197.3l.6-.2v.5a.37 .37 0 0 1-.5 .2 .37 .37 0 0 1-.1-.5zM204.9 199.1v-.3a.37 .37 0 0 0-.4-.4 .37 .37 0 0 0-.3 .4v.3h1.3M204.9 197.1l.5 .3 .1 .3M205.5 198.4l-.6 .3M208 196h1.3M208.5 195.5l.4 .5M209.3 197.8h.1M209.3 198.4v.7l-.7-.6a.36 .36 0 0 0-.5 .1 .36 .36 0 0 0 .2 .5M209.3 196.6v.8l-.7-.7a.36 .36 0 0 0-.5 .1 .36 .36 0 0 0 .2 .6M209.3 195.5l-.6 .3"/>
<path d="M210.3 188.7l.4-.2v1.1M210.3 189.6h.6M214 185.7l.1-.3 .3-.1 .2 .2v.5M214 185.8v-.3l-.3-.2-.2 .2v.5M214.6 194v.6l-.6-.6a.31 .31 0 0 0-.5 .1 .31 .31 0 0 0 .2 .5M217.1 191.9v-1.9l.6 1.1 .6-1.1v1.9M217.2 188.2l.3-.2 .5 .2 .1 1.2a.52 .52 0 0 1-.5 .5 .52 .52 0 0 1-.5-.5zM217.9 189.4l.4 .5M218.8 188.8h.6a.52 .52 0 0 1 .4 .6 .52 .52 0 0 1-.5 .5 .52 .52 0 0 1-.5-.5zM219.1 191.9v-1.9l.6 1.1 .7-1.1v1.9M219.6 188a.85 .85 0 0 0-.8 .8M220.6 180.5l.3-.2v1.1"/>
<path d="M220.6 181.4h.6M222 190.2a.48 .48 0 0 0-.8-.1 .48 .48 0 0 0 .1 .7l.5 .3a.47 .47 0 0 1 .1 .7 .47 .47 0 0 1-.7 0l-.2-.1M223.5 190.2a.47 .47 0 0 0-.7-.1 .47 .47 0 0 0 0 .7l.6 .3a.47 .47 0 0 1 .1 .7 .47 .47 0 0 1-.7 0l-.2-.1M226.1 190.2l.3-.2a1.1 1.1 0 0 1 0 1.9 1.19 1.19 0 0 1-.3-1.7zM226.3 186.1l.1-.3h.4l.1 .6M226.3 186.2v-.3l-.3-.2-.2 .2v.5M226.8 190.5l-.8 1M228.6 190h-1v.9h.6a.53 .53 0 0 1 .4 .5 .53 .53 0 0 1-.4 .5h-.6M229.5 190.2l.3-.2a1.1 1.1 0 0 1 0 1.9 1.17 1.17 0 0 1-.3-1.7zM230.2 190.5l-.8 1M230.9 191.2h1.3M231.4 188.9l.4-.3v1.3"/>
<path d="M231.4 189.9h.7M232.2 182l.3-.2 .5 .2 .1 1.2a.52 .52 0 0 1-.5 .5 .52 .52 0 0 1-.5-.5zM232.7 188.9a.37 .37 0 0 1 .5-.3 .37 .37 0 0 1 .1 .6l-.6 .7h.7M232.9 183.3l.4 .4M232.9 190v1.9h.9M233.8 181.5v-1.9l.7 1 .6-1v1.9M233.9 188.6l.4 1.3 .4-1.3M234.3 191.2h1.3M234.8 181.8h-1.1v.9h.7a.55 .55 0 0 1 .4 .5 .55 .55 0 0 1-.4 .5h-.7M235.1 190h.6M235.9 180.6h.5a.52 .52 0 0 0 .5-.5 .52 .52 0 0 0-.5-.5h-.5v1.9M236.1 190h1.1"/>
<path d="M236.2 189.2h.6M236.6 190v1.9M236.8 188.6h-.6v1.3M237.2 189.9l.5-1.3 .4 1.3M237.3 189.6h.7M237.8 191.1h.5a.53 .53 0 0 0 .5-.5 .53 .53 0 0 0-.5-.6h-.5v1.9M238 180.4a.52 .52 0 0 1 .5 .5 .52 .52 0 0 1-.5 .6h-.5M239.3 188.6v1.3l-.7-1.3v1.3M239.9 188.9a.37 .37 0 0 1 .5-.3 .37 .37 0 0 1 .1 .6l-.6 .7h.7M240.1 180l-.8 1M241.9 180.6l-.2 .6-.6 .3M243.6 180.6l-.2 .6-.6 .3"/>
<path d="M245.7 180.7h1.3M247.6 180l.5-.4v1.9M247.6 181.5h1.1M249.8 180.4a.52 .52 0 0 1 .5 .5 .52 .52 0 0 1-.5 .6h-.5M50.1 205.5l-.7 .1v.9l.2 .3h.5v-.7h-.2M51.5 205.5v1.3l-.7-1.3v1.3M52.1 205.5h.5l.2 .2v.9l-.2 .2h-.5zM58.3 205.5l-.6 .1-.1 .9 .2 .3h.5v-.7h-.2M59.7 205.5v1.3l-.8-1.3v1.3M60.3 205.5h.5l.2 .2v.7l-.2 .4h-.5zM85 205.5l-.7 .1v.9l.2 .3h.5v-.7h-.2M86.3 205.5v1.3l-.7-1.3v1.3"/>
<path d="M87 205.5h.5l.2 .2v.9l-.2 .2h-.5zM206 205.5l-.7 .1v.9l.1 .3h.6v-.7h-.2M207.3 205.5v1.3l-.7-1.3v1.3M208 205.5h.5l.2 .2v.9l-.2 .2h-.5zM214.2 205.5l-.7 .1v.9l.2 .3h.5v-.7h-.2M215.5 205.5v1.3l-.7-1.3v1.3M216.2 205.5h.5l.2 .2v.7l-.2 .4h-.5z"/>
<circle cx="117.9" cy="61.6" r=".25"/>
<circle cx="117.9" cy="62.2" r=".31"/>
<circle cx="132.7" cy="68.7" r=".25"/>
<circle cx="132.7" cy="69.2" r=".31"/>
<circle cx="135.6" cy="61.6" r=".25"/>
<circle cx="135.6" cy="62.2" r=".31"/>
<circle cx="68.9" cy="143.3" r=".43"/>
<circle cx="68.9" cy="144.2" r=".52"/>
<circle cx="224.7" cy="143.3" r=".42"/>
<circle cx="224.7" cy="144.2" r=".52"/>
<circle cx="212.7" cy="177" r=".29"/>
<circle cx="213.3" cy="177" r=".36"/>
<circle cx="68.9" cy="190.5" r=".42"/>
<circle cx="68.9" cy="191.4" r=".52"/>
<circle cx="224.7" cy="191.4" r=".52"/>
<circle cx="224.7" cy="190.5" r=".42"/>
</g>
<g fill="none" stroke="#c90d0c" stroke-width=".34">
<path d="M57.2 17.9h.8M57.6 17.9v3.7M61.2 17.9v3.7l-2.1-3.7v3.7M62.4 20a2 2 0 0 0 1.8-.3 1.05 1.05 0 0 0 .2-1.2 1.05 1.05 0 0 0-.9-.6h-1.1v3.7M65.5 17.9v2.7a1.05 1.05 0 0 0 1 1 1.05 1.05 0 0 0 1.1-1v-2.7M68.5 17.9h2.1M69.5 17.9v3.7M99.1 19.7h4.1v10.3h-4.1zM211.3 18.2a1.05 1.05 0 0 1 1.2-.2 1.05 1.05 0 0 1 .6 .9v1.7a1.05 1.05 0 0 1-1 1 1.05 1.05 0 0 1-1.1-1v-2zM214.2 17.9v2.7a1.05 1.05 0 0 0 1 1 1.05 1.05 0 0 0 1.1-1v-2.7M217.1 17.9h2.1M218.2 17.9v3.7"/>
<path d="M220.1 20a2 2 0 0 0 1.8-.3 1.05 1.05 0 0 0 .2-1.2 1.05 1.05 0 0 0-.9-.6h-1.1v3.7M223.2 17.9v2.7a1.05 1.05 0 0 0 1.1 1 1.05 1.05 0 0 0 1-1v-2.7M226.2 17.9h2.1M227.2 17.9v3.7M57.2 21.6h.8M36.7 112.2a1.88 1.88 0 0 0 1.8-.3 1.04 1.04 0 0 0 .2-1.1 1.04 1.04 0 0 0-1-.6h-1v3.7M39.5 110.2l.8 3.7 .8-2.5 .9 2.5 .8-3.7M43.7 113.9v-3.7l1.2 2 1.3-2v3.7M50.6 110.2v3.7l-1.4-.1-.3-.5 .1-1.6 .6-.3h1M53 111.8v-.4h-1.2v2.5M53.8 110.2h.3v.2h-.3zM54 111.4v2.5"/>
<path d="M55 111.4l.8 2.5 .8-2.5M57.5 112.6h1.7a.88 .88 0 0 0-.6-1.2 .88 .88 0 0 0-1.1 .8l.1 1.5 .5 .2h1.1M62 111.4h1.1l.4 .4v2.1h-.9a.73 .73 0 0 1-.8-.7 .73 .73 0 0 1 .8-.7h.9M64.7 113.9v-2.5h1l.6 .3 .1 .3v1.9M69.2 110.2v3.7l-1.5-.1-.2-.5 .1-1.6 .5-.3h1.1M73.3 111.6l-.3-.1a.68 .68 0 0 0-.8-.1 .68 .68 0 0 0-.3 .8l.3 .3 1 .4a.55 .55 0 0 1 .4 .6 .55 .55 0 0 1-.6 .4l-1.1-.2M74.5 112.6h1.7a.88 .88 0 0 0-.6-1.2 .88 .88 0 0 0-1.1 .8l.2 1.5 .5 .2h1M77.3 113.9v-2.5h1.1l.5 .3 .1 .3v1.9M81.6 111.6l-.4-.1a.65 .65 0 0 0-.9 0 .65 .65 0 0 0-.1 .9l1.2 .5a.55 .55 0 0 1 .4 .6 .55 .55 0 0 1-.6 .4l-1.1-.2M82.7 112.6h1.7a.89 .89 0 0 0-.6-1.2 .89 .89 0 0 0-1.1 .8l.2 1.5 .5 .2h1M116.7 110.2h2.1M117.7 110.2v3.7"/>
<path d="M119.8 111.4h1l.4 .4v2.1h-.9a.73 .73 0 0 1-.8-.7 .73 .73 0 0 1 .8-.7h.9M123.8 111.4h-1.1l-.3 .3-.1 .3 .1 1.7 .5 .2h.9M124.8 111.4h1l.5 .3 .1 2.2M124.8 110.2v3.7M130.7 111.6l-.4-.1a.65 .65 0 0 0-.9 0 .65 .65 0 0 0-.1 .9l1.3 .5a.55 .55 0 0 1 .3 .6 .55 .55 0 0 1-.6 .4l-1.1-.2M131.8 112.6h1.7a.89 .89 0 0 0-.6-1.2 .89 .89 0 0 0-1.1 .8l.2 1.5 .5 .2h1M134.6 113.9v-2.5h1.1l.5 .3 .1 2.2M138.9 111.6l-.3-.1a.68 .68 0 0 0-.9-.1 .68 .68 0 0 0-.3 .8l.3 .3 1 .4a.55 .55 0 0 1 .4 .6 .55 .55 0 0 1-.6 .4l-1.1-.2M140.1 112.6h1.6a.88 .88 0 0 0-.6-1.2 .88 .88 0 0 0-1 .8l.1 1.5 .5 .2h1M194.6 113.9h2.1M194.6 111l1-.8v3.7M197.7 111a1.04 1.04 0 0 1 1.3-.8 1.04 1.04 0 0 1 .6 1.4l-1.9 2.3h2.1"/>
<path d="M200.5 110.2l1.3 3.7 1.3-3.7M206.9 111.6l-.3-.1a.65 .65 0 0 0-.9 0 .65 .65 0 0 0-.1 .9l1.2 .5a.55 .55 0 0 1 .4 .6 .55 .55 0 0 1-.6 .4l-1.1-.2M208 111.4l.7 2.5 .6-1.7 .6 1.7 .6-2.5M211.4 110.2h.2v.2h-.2zM211.5 111.4v2.5M212.4 111.4h1.3M212.9 110.2v3.3l.2 .3 .6 .1M216.1 111.4h-1.1l-.3 .3-.1 .3 .1 1.7 .5 .2h.9M217.1 111.4h1l.5 .3 .1 .3v1.9M217.1 110.2v3.7M219.8 110.2h.2v.2h-.2zM219.9 111.4v2.5"/>
<path d="M221.2 113.9v-2.5h1l.5 .3 .1 .3v1.9M225.6 113.9h-1l-.6-.2-.1-1.7 .3-.5 1.4-.1v3.2l-.1 .3-.3 .2-1.1 .1M228.1 111.4h1.3M229.4 110.2l-.6 .1-.2 .3-.1 3.3M230.2 111.8a.84 .84 0 0 1 1-.4 .84 .84 0 0 1 .6 .8 1.44 1.44 0 0 1-.3 1.5 .84 .84 0 0 1-.9 .1 .84 .84 0 0 1-.5-.7zM234.1 111.8v-.4h-1.2v2.5M236.5 110.2h1.3a.84 .84 0 0 1 .8 .8 .84 .84 0 0 1-.8 .8h-.8M237.6 111.8a1.05 1.05 0 0 1 1 1.1 1.05 1.05 0 0 1-1 1h-1.1M239.7 113.9h1.1l.5-.2 .1-1.7-.3-.5-1.4-.1v3.8M242.4 110.2h.2v.2h-.2zM242.5 111.4v2.5M243.7 113.9v-2.5h1.1l.5 .3 .1 .3v1.9"/>
</g>
<g fill="none" stroke="#c90d0c" stroke-width=".2">
<path d="M108.3 15.7v2M153.4 5.4v2.1M153.4 9.5v2.1l.8 .1-1.6 .6 1.6 .5-1.6 .5 1.6 .5-1.6 .5 1.6 .5-1.6 .5 .8 .4v2M102.2 28h4.1M102.2 25.9h4.1M102.2 23.9h4.1M102.2 21.8h4.1M108.3 32.1v2M153.4 28v2M154.5 23.9h2M154.5 21.8h2M219.1 38.2h4.1"/>
<path d="M219.1 34.1h4.1M59.1 56.7v2M102.2 44.4v2M108.3 44.4v2M114.5 44.4v2M116.5 50.5h2.1M116.5 52.6h2.1M116.5 58.7h2.1M116.5 56.7h2.1M116.5 54.6h2.1M135 50.5h2M135 52.6h2"/>
<path d="M135 58.7h2M135 56.7h2M159.6 57.8l.9 .3-.9 .4M161.8 57.9h.5M162.3 57.3h-.5v1.4M162.9 57.8h.3l.2 .2v.5l-.2 .2-.4-.2zM164.4 57.9v-.1h-.4v.9M166 57.8h-.5v.2l.5 .4v.1l-.5 .1M166.6 58.7l.6-.2v-.5l-.1-.2h-.5v1.3M167.7 58.2h.6a.31 .31 0 0 0-.2-.4 .31 .31 0 0 0-.4 .3v.4l.6 .2M168.8 58.2h.6a.31 .31 0 0 0-.2-.4 .31 .31 0 0 0-.4 .3v.4l.6 .2M170.5 57.3v1.4l-.5-.1-.1-.2v-.5l.6-.1"/>
<path d="M172.2 57.9v-.1h-.5v.9M172.6 58.2h.5a.3 .3 0 0 0-.2-.4 .3 .3 0 0 0-.3 .3v.4l.5 .2M173.7 57.8h.4l.1 .2v.7l-.4-.1-.1-.4 .5-.1M175.4 57.3v1.4l-.5-.1-.1-.7 .6-.1M175.9 57.3l.1 .1zM175.9 57.8v.9M176.5 58.7v-.9l.5 .1 .1 .8M178.2 58.7l-.5-.2v-.7h.5v1.1l-.1 .2h-.4M217 48.5v2M219.1 46.4h4.1M219.1 42.3h4.1M59.1 75.1v2.1"/>
<path d="M61.2 60.8h4M61.2 64.9h4.1M61.2 69h4.1M61.2 73.1h4.1M65.2 60.8h.1M116.5 62.8h2.1M116.5 64.9h2.1M116.5 66.9h2.1M116.5 69h2.1M116.5 71h2.1M116.5 73.1h2.1M116.5 75.1h2.1"/>
<path d="M116.5 77.2h2.1M116.5 79.2h2.1M135 60.8h2M135 62.8h2M135 64.9h2M135 66.9h2M135 69h2M135 71h2M135 73.1h2M135 75.1h2M135 77.2h2M135 79.2h2"/>
<path d="M159.6 78.3l.9 .4-.9 .3M159.6 72.1l.9 .4-.9 .4M159.6 63.9l.9 .4-.9 .4M161.8 78.4h.5M161.8 72.3h.5M161.8 64.1h.5M162.3 63.5h-.5v1.3M162.3 71.7h-.5v1.3M162.3 77.9h-.5v1.3M162.9 78.3h.3l.2 .1v.6l-.2 .1-.4-.1zM162.9 72.2l.3-.1 .2 .2v.5l-.2 .2-.4-.2zM162.9 64l.3-.1 .2 .2v.5l-.2 .2-.4-.2z"/>
<path d="M164.4 64.1v-.2h-.4v.9M164.4 72.3v-.2h-.4v.9M164.4 78.4v-.1h-.4v.9M165.5 63.5h.5l.2 .2-.2 .4h-.4M165.5 78.6h.4a.36 .36 0 0 0 .4-.4 .36 .36 0 0 0-.4-.3h-.4v1.3M165.5 72.4h.4a.37 .37 0 0 0 .4-.3 .37 .37 0 0 0-.4-.4h-.4v1.3M165.8 64.1a.37 .37 0 0 1 .4 .3 .37 .37 0 0 1-.4 .4h-.3M166.7 77.9l.3 1.3 .3-.9 .3 .9 .3-1.3M166.7 71.7l.3 1.3 .3-.9 .3 .9 .3-1.3M166.8 64.3h.8M168.2 64.8l.6-.1-.1-.7-.5-.1v1.3M168.4 73v-1.3l.4 .7 .5-.7v1.3"/>
<path d="M168.4 79.2v-1.3l.4 .7 .5-.7v1.3M169.2 63.5l.1 .1zM169.3 63.9v.9M169.8 64.8v-.9l.6 .2v.7M171 78.4l-.3-.1-.2 .2 .6 .4v.2h-.6M171.1 71.7v1.3h-.5l-.1-.8 .6-.1M171.6 63.9h.4M171.6 78.7h.6a.31 .31 0 0 0-.2-.4 .31 .31 0 0 0-.4 .3l.1 .5 .5 .1M172 63.5l-.3 .1v1.2M172.1 72.3v-.2h-.4v.9M172.4 63.9l.5 .2v.7l-.5-.1v-.3l.5-.1M172.5 71.7l.1 .1z"/>
<path d="M172.5 72.1v.9M172.7 79.2v-.9l.6 .1v.8M173 72.1l.3 .9 .3-.9M173.5 64.8v-.9l.6 .2v.7M174 71.7l.1 .1zM174 72.1v.9M174.4 78.4l-.3-.1-.2 .2 .5 .4 .1 .2h-.6M174.6 73v-.9l.5 .1 .1 .8M174.9 77.9h.1zM175 78.3v.9M175.5 79.2v-.9l.6 .1v.8M175.9 64l-.4-.1-.2 .2 .6 .4v.2h-.6"/>
<path d="M176.3 73l-.6-.1 .1-.7 .5-.1v1.1l-.1 .2h-.4M176.5 63.9v.8l.2 .1h.4v-.9M177.2 79.2l-.5-.1-.1-.6 .2-.2h.4v1.1l-.1 .2h-.4M177.7 72.2l.2-.1 .2 .2v.5l-.2 .2-.4-.3zM177.7 64.8l.5-.1-.1-.7-.4-.1v1.3M178.6 78.3h.2l.2 .1-.1 .7h-.2l-.2-.1zM178.7 73v-.9l.5 .1 .1 .8M178.8 64.8l.6-.1-.1-.7-.5-.1v1.3M179.6 79.2v-.9l.5 .1 .1 .8M179.8 71.7v1.1l.2 .2M180 64l.3-.1 .1 .2v.5l-.1 .2-.4-.2zM180.4 72.1l.3 .9"/>
<path d="M180.7 77.9v1l.3 .3M181 72.1l-.4 1.3h-.2M181.4 78.3l.3 .9M181.5 64.1v-.2h-.5v.9M181.8 63.9h.4M181.9 63.5v1.2l.3 .1M181.9 78.3l-.4 1.3h-.1M217 77.2v2M219.1 62.8h4.1M219.1 66.9h4.1M219.1 71h4.1M219.1 75.1h4.1"/>
<path d="M114.5 85.4v2M227.2 118.2v2M59.1 136.6v4.2M139.1 124.3v2.1l.8 .2-1.7 .5 1.7 .5-1.7 .5 1.7 .5-1.7 .6 1.7 .5-1.7 .5 .9 .3v2M139.1 120.2v2.1M214.9 124.3v2.1l.9 .2-1.7 .5 1.7 .5-1.7 .5 1.7 .5-1.7 .6 1.7 .5-1.7 .5 .8 .3v2M214.9 136.6l.1 4.2M219.1 134.6h4.9M227.2 130.5l.1 4.1M227.2 136.2v4.5M38.6 142.8h2l.3-.8 .5 1.6 .6-1.6 .5 1.6 .5-1.6 .5 1.6 .5-1.6 .5 1.6 .2-.8h2.1M50.9 144.8v2.1l.8 .2-1.6 .5 1.6 .5-1.6 .5 1.6 .5-1.6 .5 1.6 .6-1.6 .5 .8 .3v2"/>
<path d="M50.9 155.1v2M52.9 142.8h4.2M59.1 155.1v2M59.1 144.9v4M85.7 140.7v2.1l.9 .2-1.7 .5 1.7 .5-1.7 .5 1.7 .6-1.7 .5 1.7 .5-1.7 .5 .8 .3v2M85.7 155.1v2M194.4 142.8h2.1l.3-.8 .5 1.6 .5-1.6 .5 1.6 .5-1.6 .6 1.6 .5-1.6 .5 1.6 .2-.8h2M206.7 144.8v2.1l.9 .2-1.7 .5 1.7 .5-1.7 .5 1.7 .5-1.7 .5 1.7 .6-1.7 .5 .8 .3v2M206.7 155.1v2M208.8 142.8h4.1M212.9 142.8h.1M214.9 155.1v2"/>
<path d="M215 144.9l-.1 4M139.1 167.4v2M139.1 171.5v2l.8 .3-1.7 .5 1.7 .5-1.7 .5 1.7 .5-1.7 .5 1.7 .5-1.7 .5 .9 .4v2M214.9 171.5v2l.9 .3-1.7 .5 1.7 .5-1.7 .5 1.7 .5-1.7 .5 1.7 .5-1.7 .5 .8 .4v2M227.2 165.4v2M227.2 177.7v4.1M38.6 189.9h2l.3-.8 .5 1.7 .6-1.7 .5 1.7 .5-1.7 .5 1.7 .5-1.7 .5 1.7 .2-.9h2.1M50.9 192v2.1l.8 .2-1.6 .5 1.6 .5-1.6 .5 1.6 .5-1.6 .5 1.6 .5-1.6 .5 .8 .4v2M52.9 189.9l4.2 .1M59.1 183.8v4.1M59.1 192v4.1M85.7 187.9v2l.9 .3-1.7 .5 1.7 .5-1.7 .5 1.7 .5-1.7 .5 1.7 .5-1.7 .5 .8 .4v2"/>
<path d="M194.4 189.9h2.1l.3-.8 .5 1.7 .5-1.7 .5 1.7 .5-1.7 .6 1.7 .5-1.7 .5 1.7 .2-.9h2M206.7 192v2.1l.9 .2-1.7 .5 1.7 .5-1.7 .5 1.7 .5-1.7 .5 1.7 .5-1.7 .5 .8 .4v2M208.8 189.9l4.1 .1M214.9 183.8l.1 4.1M215 192l-.1 4.1M219.1 181.8h4.9M227.2 183.4v4.5M227.2 181.8h.1M50.9 202.2v2.1M59.1 202.2v2.1M85.7 202.2v2.1M206.7 202.2v2.1"/>
<path d="M214.9 202.2v2.1"/>
</g>
<g fill="none" stroke="#c90d0c" stroke-width=".21">
<path d="M107.3 17.2l1-1.5 1 1.5M152.4 6.9l1-1.5 1.1 1.5M107.3 34.1h2l-1 1zM152.4 30h2.1l-1.1 1zM223.1 30h4.1v20.5h-4.1zM58.1 58.2l1-1.5 1 1.5M58.1 57.2l1-1.6 1 1.6M65.2 56.7h4.1v20.5h-4.1zM101.1 45.9l1.1-1.5 1 1.5M101.1 44.9l1.1-1.6 1 1.6M107.3 45.9l1-1.5 1 1.5M113.4 45.9l1.1-1.5 1 1.5"/>
<path d="M118.6 48.5h16.4v32.8h-16.4zM216 50.5h2l-1 1zM223.1 58.7h4.1v20.5h-4.1zM58.1 77.2h2l-1 1zM216 79.2h2l-1 1zM113.4 87.4h2.1l-1 1.1zM226.2 119.7l1-1.5 1.1 1.5M226.2 118.7l1-1.5 1.1 1.5M138 121.8l1.1-1.6 1 1.6M49.9 157.1h2l-1 1.1zM58.1 157.1h2l-1 1.1zM84.7 157.1h2.1l-1.1 1.1z"/>
<path d="M205.7 157.1h2.1l-1.1 1.1zM213.9 157.1h2.1l-1.1 1.1zM138 168.9l1.1-1.5 1 1.5M226.2 166.9l1-1.5 1.1 1.5M226.2 165.9l1-1.6 1.1 1.6M49.9 204.3h2l-1 1zM58.1 204.3h2l-1 1zM84.7 204.3h2.1l-1.1 1zM205.7 204.3h2.1l-1.1 1zM213.9 204.3h2.1l-1.1 1z"/>
</g>
<path d="M224.8 33.7h1.4v.8h-1.4zM224.8 37.8h1.4v.8h-1.4zM224.8 41.9h1.4v.8h-1.4zM224.8 46h1.4v.8h-1.4zM66.9 60.3h1.4v.9h-1.4zM66.9 64.5h1.4v.8h-1.4zM66.9 68.6h1.4v.8h-1.4zM66.9 72.7h1.4v.8h-1.4zM224.8 62.4h1.4v.8h-1.4zM224.8 66.5h1.4v.8h-1.4zM224.8 70.6h1.4v.8h-1.4zM224.8 74.7h1.4v.8h-1.4z" fill="none" stroke="#c90d0c" stroke-width=".83"/>
<g fill="none" stroke="#c90d0c" stroke-width=".42">
<path d="M223.1 38.2h1.5M223.1 34.1h1.5M223.1 46.4h1.5M223.1 42.3h1.5M65.2 73.1h1.5M65.2 69h1.5M65.2 64.9h1.5M65.2 60.8h1.5M223.1 75.1h1.5M223.1 71h1.5M223.1 66.9h1.5M223.1 62.8h1.5"/>
<path d="M224 132.5v4.1M224.6 132.5v.8M224.6 134.2v.8M224.6 135.8v.8M224.6 132.9h4.1v3.3h-4.1M224.8 134.6h2M226 134l1 .6-1 .6zM226.2 134.2v.6M228.3 134.2h.8M228.7 134.2l.4 .8h-.8zM57 140.7v4.1M57 143.8l2.1 1"/>
<path d="M58.3 144l.8 .8-1.2-.2zM59.1 140.7l-2.1 1.1M212.9 140.7v4.1M212.9 143.8l2 1M214.1 144l.8 .8-1.2-.2zM214.9 140.7l-2 1.1M224 179.7v4.1M224.6 179.7v.8M57 187.9v4.1M57 191l2.1 1M58.3 191.2l.8 .8-1.2-.2zM59.1 187.9l-2.1 1"/>
<path d="M212.9 187.9v4.1M212.9 191l2 1M214.1 191.2l.8 .8-1.2-.2zM214.9 187.9l-2 1M224.6 181.3v.9M224.6 183v.8M224.6 180.1h4.1v3.3h-4.1M224.8 181.8h2M226 181.1l1 .7-1 .6zM226.2 181.3v.6M228.3 181.3h.8M228.7 181.3l.4 .9h-.8z"/>
</g>
<g fill="#c90d0c" stroke="#c90d0c" stroke-width=".2">
<path d="M227 136.1a.31 .31 0 0 1 .4-.1 .31 .31 0 0 1 .1 .3 .3 .3 0 0 1-.3 .2 .3 .3 0 0 1-.3-.3l.4-.1 .1 .1h-.5z" fill-rule="evenodd"/>
<path d="M227 132.8a.31 .31 0 0 1 .4-.1 .31 .31 0 0 1 .1 .3 .3 .3 0 0 1-.3 .2 .3 .3 0 0 1-.3-.3l.4-.1 .1 .2-.5-.1z" fill-rule="evenodd"/>
<path d="M227 183.2a.31 .31 0 0 1 .4-.1 .31 .31 0 0 1 .1 .4l-.2 .2h-.2l-.2-.3h.5l-.2 .1-.3-.1z" fill-rule="evenodd"/>
<path d="M227 179.9a.31 .31 0 0 1 .4-.1 .31 .31 0 0 1 .1 .4l-.2 .2h-.2l-.2-.3h.5l-.2 .1-.3-.1z" fill-rule="evenodd"/>
</g>
<path d="M101.1 23.9h1.1M101.1 25.9h1.1M101.1 28h1.1M101.1 21.8h1.1" fill="none" stroke="#c90d0c" stroke-width=".51"/>
<g fill="#c90d0c" stroke="#c90d0c" stroke-width=".2">
<path d="M156.5 21.6h1.4v.4h-1.4z"/>
<path d="M156.5 23.6h1.4v.5h-1.4z"/>
</g>
<g fill="none" stroke="#0dab76" stroke-width=".2">
<path d="M108.3 17.7v8.2h-2M153.4 7.5v2M153.4 17.7v4.1M106.3 28h2v4.1M106.3 23.9h18.4M106.3 21.8h18.4M139.1 21.8h15.4M154.5 23.9h-1.1v4.1M194.4 34.1h24.7M194.4 38.2h24.7M59.1 58.7v10.3h2.1M102.2 46.4v8.2h14.3"/>
<path d="M108.3 46.4v16.4h8.2M108.3 52.6h8.2M114.5 46.4v4.1h2M116.5 56.7h-2v28.7M137 56.7h20.5M137 58.7h20.5M194.4 42.3h24.7M219.1 46.4h-2.1v2.1M36.5 60.8h24.7M36.5 64.9h24.7M61.2 73.1h-2.1v2M94 69h22.5"/>
<path d="M94 77.2h22.5M94 71h22.5M137 64.9h20.5M137 73.1h20.5M137 77.2h20.5M137 62.8h20.5M137 79.2h20.5M137 71h20.5M194.4 62.8h24.7M194.4 66.9h24.7M194.4 71h24.7M219.1 75.1h-2.1v2.1"/>
<path d="M28.3 134.6h63.6M59.1 134.6v2M85.7 134.6v6.1M106.3 134.6h53.3M139.1 122.3v2M139.1 132.5v2.1M214.9 132.5v4.1M214.9 134.6h4.2M227.2 122.3h-12.3v2M227.2 120.2v10.3M28.3 142.8h10.3M46.8 142.8h6.1"/>
<path d="M50.9 142.8v2M50.9 153v2.1M59.1 148.9v6.2M85.7 148.9v6.2M180.1 142.8h14.3M202.6 142.8h6.2M206.7 142.8v2M206.7 153v2.1M214.9 148.9v6.2M227.2 140.7v2.1h18.5M139.1 169.4v2.1M139.1 179.7v2.1"/>
<path d="M214.9 179.7v4.1M227.2 169.4h-12.3v2.1M227.2 167.4v10.3M28.3 181.8h63.6M28.3 189.9h10.3M46.8 189.9h6.1M50.9 189.9v2.1M59.1 181.8v2M59.1 196.1v6.1M85.7 181.8v6.1M85.7 196.1v6.1M106.3 181.8h53.3"/>
<path d="M180.1 189.9h14.3M202.6 189.9h6.2M206.7 189.9v2.1M214.9 196.1v6.1M214.9 181.8h4.2M227.2 187.9v2h18.5M50.9 200.2v2M206.7 200.2v2"/>
</g>
<g fill="#0dab76" stroke="#0dab76" stroke-width=".2">
<circle cx="227.2" cy="122.3" r=".4"/>
<circle cx="227.2" cy="169.4" r=".4"/>
<circle cx="85.7" cy="134.6" r=".4"/>
<circle cx="59.1" cy="134.6" r=".4"/>
<circle cx="139.1" cy="134.6" r=".4"/>
<circle cx="85.7" cy="181.8" r=".4"/>
<circle cx="59.1" cy="181.8" r=".4"/>
<circle cx="139.1" cy="181.8" r=".4"/>
<circle cx="214.9" cy="134.6" r=".4"/>
<circle cx="214.9" cy="181.8" r=".4"/>
<circle cx="153.4" cy="21.8" r=".4"/>
<circle cx="108.3" cy="52.6" r=".4"/>
<circle cx="50.9" cy="142.8" r=".4"/>
<circle cx="50.9" cy="189.9" r=".4"/>
<circle cx="206.7" cy="142.8" r=".4"/>
<circle cx="206.7" cy="189.9" r=".4"/>
</g>
<use href="#words"/>
</svg>
